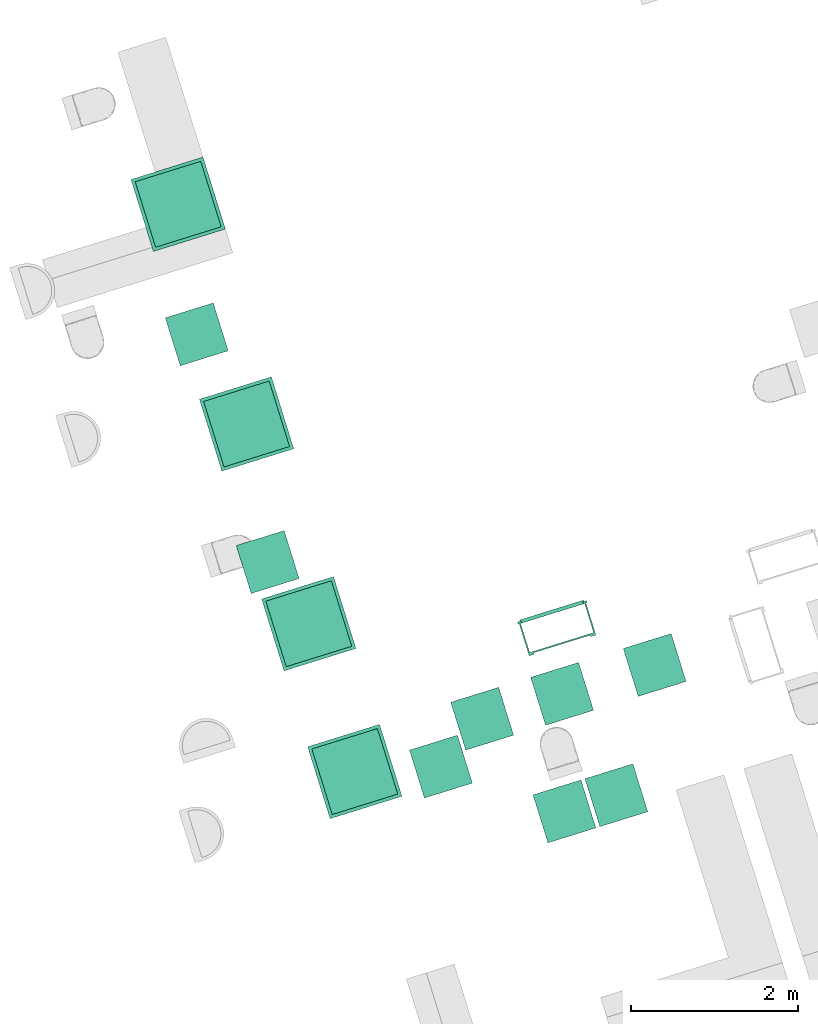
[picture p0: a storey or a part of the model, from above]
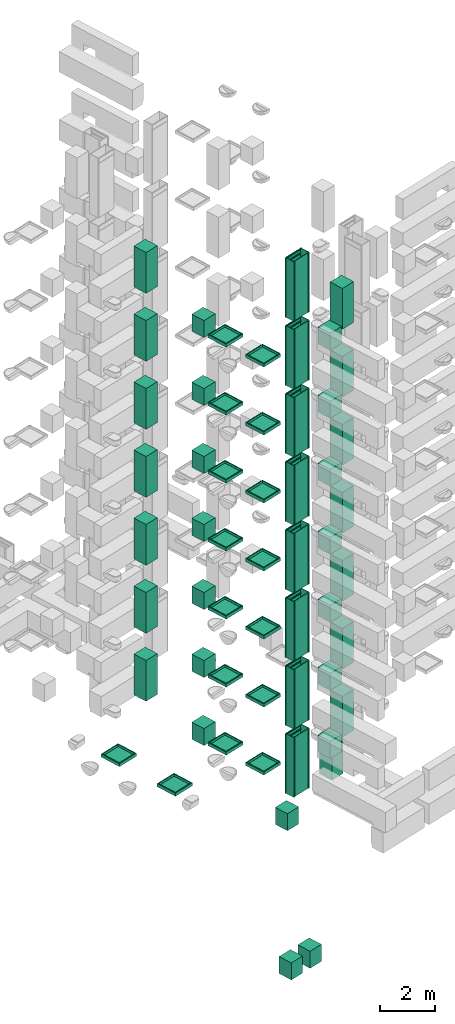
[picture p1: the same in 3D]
Properties of the parts of a building model (IFC4), part 1 of 2

# File
Description: ViewDefinition [ReferenceView_V1.2], RevitIdentifiers [ContentGUID: 7b0fba1c-e461-43e6-a004-74300536da52, VersionGUID: 7265df18-267a-4dc0-a71b-dcb3ef465860, NumberOfSaves: 301], Options [Excluded Entities: IfcGroup;], CoordinateReference [CoordinateBase: Survey Point, ProjectSite: Internal]
File name: MiniBIM 3.1 DO_02_VORM.ifc
Time: 2025-11-03T19:47:52+01:00
Organization: VORM Holding B.V.
Written by: IfcOpenShell 0.8.2
Made in: Bonsai 0.8.2

# IfcProject, 0000
LongName: Voorbeelmodel MiniBIM 3.1 DO-fase; Phase: PROJECTFASE

# IfcSite, Schiehaven
RefLatitude: 51, 54, 13, 78253; RefLongitude: 4, 27, 15, 99642; RefElevation: 3.5 m
Pset_SiteCommon - Reference: Project Information

# IfcBuilding, VORM huis
LongName: VORM huis
Pset_BuildingCommon - Reference: Project Information; NumberOfStoreys: 11; IsLandmarked: no
Pset_BuildingElementProxyCommon - Reference: Project Information; IsExternal: no
Pset_BuildingStoreyCommon - Reference: Project Information; AboveGround: no
Pset_BuildingSystemCommon - Reference: Project Information

# IfcBuildingStorey: Level:Level bouwniveau (PBP) (11)
In: VORM huis
Pset_BuildingStoreyCommon - Reference: Level bouwniveau (PBP)
Name | LongName | Elevation (m) | EntranceLevel | AboveGround
-1 kelder | -1 kelder | -3.2 | no | no
00 begane grond | begane grond | 0 | yes | yes
01 eerste verdieping | 01 eerste verdieping | 3.9 | no | yes
02 tweede verdieping | 02 tweede verdieping | 6.9 | no | yes
03 derde verdieping | 03 derde verdieping | 9.9 | no | yes
04 vierde verdieping | 04 vierde verdieping | 12.9 | no | yes
05 vijfde verdieping | 05 vijfde verdieping | 15.9 | no | yes
06 zesde verdieping | 06 zesde verdieping | 18.9 | no | yes
07 zevende verdieping | 07 zevende verdieping | 21.9 | no | yes
08 achtste verdieping | 08 achtste verdieping | 24.9 | no | yes
09 negende verdieping | 09 negende verdieping | 27.9 | no | yes

# IfcBoiler: NLRS_51_ME_WB_warmtepomp_gen:generiek (44)
Type - Classification: 51.51 (NL-SfB); Material: <Unnamed>
Pset_BoilerTypeCommon - Reference: generiek; sets with these values: 2
Name (NLRS_51_ME_WB_warmtepomp_gen:generiek:...)
1530201
1530227
1530253
1530279
1530305
1530357
1530409
1560085
1560111
1560137
1560163
1560189
1560241
1560293
1578360
1600198
1600224
1600250
1600276
1600302
1600354
1600406
1601616
1601805
1601994
1602183
1602372
1602565
1605335
1605360
1605385
1605410
1605435
1605485
1605535
1609133
1609161
1609189
1609217
1609245
1609301
1609357
1668816
1668842

# IfcBuildingElementProxy: VORM_coordinatiepunt:CRS-coordinatiepunt, CRS-coordinatiepunt
In: 00 begane grond
Type - Classification: 00.00 (NL-SfB); Material: Blauw, Wit
Pset_BuildingElementProxyCommon - IsExternal: no; Reference: CRS-coordinatiepunt
Pset_EnvironmentalImpactIndicators - Reference: CRS-coordinatiepunt
Qto_BuildingElementProxyQuantities - NetSurfaceArea: 6.92096 m2; NetVolume: 0.458368 m3

# IfcBuildingElementProxy: VORM_coordinatiepunt:Lokaal-coordinatiepunt, Lokaal-coordinatiepunt
In: 00 begane grond
Type - Classification: 00.00 (NL-SfB); Material: Blauw, Wit
Pset_BuildingElementProxyCommon - IsExternal: no; Reference: Lokaal-coordinatiepunt
Pset_EnvironmentalImpactIndicators - Reference: Lokaal-coordinatiepunt
Qto_BuildingElementProxyQuantities - NetSurfaceArea: 7.78088 m2; NetVolume: 1.00022 m3

# IfcDistributionChamberElement: NLRS_61_GM_UN_Jonka meterkast_gen:Jonka_kast (49)
Type - PredefinedType: METERCHAMBER; Classification: 61.51 centrale elektrotechnische voorzieningen; energiedistributie laagspanning ?1kV, voedingsleiding laagspanningshoofdverdeler (NL-SfB); Material: <Unnamed>
Type - Pset_ManufacturerTypeInformation - Manufacturer: Jonka o.g.
Pset_DistributionChamberElementCommon - Reference: Jonka_kast; sets with these values: 2
Qto_DistributionChamberElementBaseQuantities - GrossSurfaceArea: 0.130276 m2; NetSurfaceArea: 15.0923 m2; GrossVolume: 0.000819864 m3; NetVolume: 0.122447 m3
Name (NLRS_61_GM_UN_Jonka meterkast_gen:Jonka_kast:...)
1530198
1530224
1530250
1530276
1530302
1530354
1530406
1557295
1557339
1557385
1560082
1560108
1560134
1560160
1560186
1560238
1560290
1565796
1565820
1565844
1565868
1565892
1565940
1565988
1600199
1600225
1600251
1600277
1600303
1600355
1600407
1605322
1605347
1605372
1605397
1605422
1605472
1605522
1609134
1609162
1609190
1609218
1609246
1609302
1609358
1668766
1668794
1668820
1668847

# IfcDoor: 31_DO_buitendeur dubbel:buitendeur zelfsluitend 30min (4)
In: 00 begane grond
Type - PredefinedType: DOOR; Classification: 31.30 buitenwandopeningen; gevuld met deuren, algemeen (verzamelniveau) (NL-SfB); Material: PD_a_buitenwandopeningen, metaal_aluminium_ntb
Type - Pset_DoorCommon - IsExternal: no; FireRating: 30
OverallHeight: 2.35 m; OverallWidth: 1.965 m
Pset_DoorCommon - Reference: buitendeur zelfsluitend 30min
Pset_EnvironmentalImpactIndicators - Reference: buitendeur zelfsluitend 30min
MiniBIM ILS - BouwwerkNummer: 02
Qto_DoorBaseQuantities - Width: 1.965 m; Height: 2.35 m; Perimeter: 1.965 m; Area: 4.61775 m2
Name | Gebruiksbestemming | Orientatie
Vluchtdeur | Woonfunctie | Oost
3 x Vluchtdeur | Bijeenkomstfunctie | West

# IfcDoor: 31_DO_buitendeur enkel:buitendeur zelfsluitend 30min (2)
In: 00 begane grond
Type - PredefinedType: DOOR; Classification: 31.30 buitenwandopeningen; gevuld met deuren, algemeen (verzamelniveau) (NL-SfB); Material: PD_a_buitenwandopeningen, metaal_aluminium_ntb
Type - Pset_DoorCommon - IsExternal: no; FireRating: 30
OverallHeight: 2.35 m; OverallWidth: 1.05 m
Pset_DoorCommon - Reference: buitendeur zelfsluitend 30min
Pset_EnvironmentalImpactIndicators - Reference: buitendeur zelfsluitend 30min
MiniBIM ILS - BouwwerkNummer: 02; Gebruiksbestemming: Overige gebruiksfunctie
Qto_DoorBaseQuantities - Width: 1.05 m; Height: 2.35 m; Perimeter: 2 m; Area: 2.4675 m2
Name | Orientatie
Vluchtdeur | West
Vluchtdeur | Oost

# IfcDoor: 31_DO_buitendeur enkel:woningtoegangsdeur (3)
In: 00 begane grond
Type - PredefinedType: DOOR; OperationType: REVOLVING; Classification: 31.30 buitenwandopeningen; gevuld met deuren, algemeen (verzamelniveau) (NL-SfB); Material: PD_a_buitenwandopeningen, metaal_aluminium_ntb
Type - Woningtoegangsdeur:1 - PanelOperation: REVOLVING
Type - Pset_DoorCommon - IsExternal: no
OverallHeight: 2.35 m; OverallWidth: 1.05 m
Pset_DoorCommon - Reference: woningtoegangsdeur
Pset_EnvironmentalImpactIndicators - Reference: woningtoegangsdeur
MiniBIM ILS - BouwwerkNummer: 02; Gebruiksbestemming: Woonfunctie; Orientatie: Noord
Qto_DoorBaseQuantities - Width: 1.05 m; Height: 2.35 m; Perimeter: 2 m; Area: 2.4675 m2

# IfcDoor: 32_DO_binnendeur dubbel:binnendeur zelfsluitend 30min (6)
In: 00 begane grond
Type - PredefinedType: DOOR; Classification: 32.30 binnenwandopeningen; gevuld met deuren, algemeen (verzamelniveau) (NL-SfB); Material: PD_a_binnenwandopeningen, metaal_aluminium_ntb
Type - Pset_DoorCommon - IsExternal: no; FireRating: 30
OverallHeight: 2.35 m; OverallWidth: 1.95 m
Pset_DoorCommon - Reference: binnendeur zelfsluitend 30min
Pset_EnvironmentalImpactIndicators - Reference: binnendeur zelfsluitend 30min
Qto_DoorBaseQuantities - Width: 1.95 m; Height: 2.35 m; Perimeter: 1.95 m; Area: 4.5825 m2

# IfcDoor: 32_DO_binnendeur enkel:binnendeur (359)
Type - PredefinedType: DOOR; OperationType: REVOLVING; Classification: 32.30 binnenwandopeningen; gevuld met deuren, algemeen (verzamelniveau) (NL-SfB); Material: PD_a_binnenwandopeningen, metaal_aluminium_ntb
Type - Binnendeur:1 - PanelOperation: REVOLVING
Type - Pset_DoorCommon - IsExternal: no
OverallHeight: 2.35 m; OverallWidth: 1.05 m
Pset_DoorCommon - Reference: binnendeur
Pset_EnvironmentalImpactIndicators - Reference: binnendeur
Qto_DoorBaseQuantities - Width: 1.05 m; Height: 2.35 m; Perimeter: 2 m; Area: 2.4675 m2
Name | In
41 x Binnendeur | 02 tweede verdieping
41 x Binnendeur | 03 derde verdieping
41 x Binnendeur | 04 vierde verdieping
41 x Binnendeur | 05 vijfde verdieping
41 x Binnendeur | 06 zesde verdieping
41 x Binnendeur | 07 zevende verdieping
41 x Binnendeur | 08 achtste verdieping
49 x Binnendeur | 01 eerste verdieping
23 x Binnendeur | 00 begane grond

# IfcDoor: 32_DO_binnendeur enkel:binnendeur zelfsluitend 30min (45)
Type - PredefinedType: DOOR; Classification: 32.30 binnenwandopeningen; gevuld met deuren, algemeen (verzamelniveau) (NL-SfB); Material: PD_a_binnenwandopeningen, metaal_aluminium_ntb
Type - Pset_DoorCommon - IsExternal: no; FireRating: 30
OverallHeight: 2.35 m; OverallWidth: 1.05 m
Pset_DoorCommon - Reference: binnendeur zelfsluitend 30min
Pset_EnvironmentalImpactIndicators - Reference: binnendeur zelfsluitend 30min
Qto_DoorBaseQuantities - Width: 1.05 m; Height: 2.35 m; Perimeter: 2 m; Area: 2.4675 m2
Name | In | BouwwerkNummer
4 x Vluchtdeur | 02 tweede verdieping | 01
4 x Vluchtdeur | 03 derde verdieping | 01
4 x Vluchtdeur | 04 vierde verdieping | 01
4 x Vluchtdeur | 05 vijfde verdieping | 01
4 x Vluchtdeur | 06 zesde verdieping | 01
4 x Vluchtdeur | 07 zevende verdieping | 01
4 x Vluchtdeur | 01 eerste verdieping | 01
4 x Vluchtdeur | 08 achtste verdieping | 01
2 x Vluchtdeur | -1 kelder | 01
6 x Vluchtdeur | -1 kelder
4 x Vluchtdeur | 00 begane grond | 01
Vluchtdeur | 00 begane grond

# IfcDoor: 32_DO_binnendeur enkel:kastdeur (3)
In: 00 begane grond
Type - PredefinedType: DOOR; OperationType: REVOLVING; Classification: 32.30 binnenwandopeningen; gevuld met deuren, algemeen (verzamelniveau) (NL-SfB); Material: PD_a_binnenwandopeningen, metaal_aluminium_ntb
Type - Binnendeur:1 - PanelOperation: REVOLVING
Type - Pset_DoorCommon - IsExternal: no
OverallHeight: 2.35 m; OverallWidth: 0.95 m
Pset_DoorCommon - Reference: kastdeur
Pset_EnvironmentalImpactIndicators - Reference: kastdeur
Qto_DoorBaseQuantities - Width: 0.95 m; Height: 2.35 m; Perimeter: 1.8 m; Area: 2.2325 m2

# IfcDoor: 32_DO_binnendeur enkel:woningtoegangsdeur (46)
Type - PredefinedType: DOOR; OperationType: REVOLVING; Classification: 32.30 binnenwandopeningen; gevuld met deuren, algemeen (verzamelniveau) (NL-SfB); Material: PD_a_binnenwandopeningen, metaal_aluminium_ntb
Type - Woningtoegangsdeur:1 - PanelOperation: REVOLVING
Type - Pset_DoorCommon - IsExternal: no
OverallHeight: 2.35 m; OverallWidth: 1.05 m
Pset_DoorCommon - Reference: woningtoegangsdeur
Pset_EnvironmentalImpactIndicators - Reference: woningtoegangsdeur
MiniBIM ILS - BouwwerkNummer: 02
Qto_DoorBaseQuantities - Width: 1.05 m; Height: 2.35 m; Perimeter: 2 m; Area: 2.4675 m2
Name | In
6 x Woningtoegangsdeur | 02 tweede verdieping
6 x Woningtoegangsdeur | 03 derde verdieping
6 x Woningtoegangsdeur | 04 vierde verdieping
6 x Woningtoegangsdeur | 05 vijfde verdieping
6 x Woningtoegangsdeur | 06 zesde verdieping
6 x Woningtoegangsdeur | 07 zevende verdieping
6 x Woningtoegangsdeur | 08 achtste verdieping
4 x Woningtoegangsdeur | 01 eerste verdieping

# IfcDoor: 66_WI_liftdeur:brandweerlift - eenzijdig toegankelijk (2)
In: -1 kelder
Type - PredefinedType: DOOR; Classification: 66.10 transport; liftinstallaties, algemeen (verzamelniveau) (NL-SfB); Material: metaal_aluminium_ntb
OverallHeight: 2.4 m; OverallWidth: 1 m
Pset_DoorCommon - IsExternal: no; Reference: brandweerlift - eenzijdig toegankelijk
Pset_EnvironmentalImpactIndicators - Reference: brandweerlift - eenzijdig toegankelijk
MiniBIM ILS - BouwwerkNummer: 01
Qto_DoorBaseQuantities - Width: 1 m; Height: 2.4 m; Perimeter: 1.1 m; Area: 2.4 m2

# IfcDoor: 66_WI_liftdeur:brandweerlift - tweezijdig toegankelijk (18)
Type - PredefinedType: DOOR; Classification: 66.10 transport; liftinstallaties, algemeen (verzamelniveau) (NL-SfB); Material: metaal_aluminium_ntb
OverallHeight: 2.4 m; OverallWidth: 1 m
Pset_DoorCommon - IsExternal: no; Reference: brandweerlift - tweezijdig toegankelijk
Pset_EnvironmentalImpactIndicators - Reference: brandweerlift - tweezijdig toegankelijk
MiniBIM ILS - BouwwerkNummer: 01
Qto_DoorBaseQuantities - Width: 1 m; Height: 2.4 m; Perimeter: 1.1 m; Area: 2.4 m2
Name | In
2 x Brandweerlift | 02 tweede verdieping
2 x Brandweerlift | 03 derde verdieping
2 x Brandweerlift | 04 vierde verdieping
2 x Brandweerlift | 05 vijfde verdieping
2 x Brandweerlift | 06 zesde verdieping
2 x Brandweerlift | 07 zevende verdieping
2 x Brandweerlift | 01 eerste verdieping
2 x Brandweerlift | 08 achtste verdieping
2 x Brandweerlift | 00 begane grond

# IfcElectricAppliance: NLRS_85_SE_UN_opstelplaats wasmachine_gen:wasdroger (48)
Type - PredefinedType: TUMBLEDRYER; Classification: 85.11 losse schoonmaakinventaris; standaard, schoonmaakapparatuur (NL-SfB); Material: <Unnamed>
Pset_ElectricApplianceTypeCommon - Reference: wasdroger; sets with these values: 2
Name (NLRS_85_SE_UN_opstelplaats wasmachine_gen:wasdroger:...)
1530205
1530231
1530257
1530283
1530309
1530361
1530413
1560088
1560114
1560140
1560166
1560192
1560244
1560296
1565801
1565825
1565849
1565873
1565897
1565945
1565993
1600197
1600223
1600249
1600275
1600301
1600353
1600405
1605334
1605359
1605384
1605409
1605434
1605484
1605534
1609132
1609160
1609188
1609216
1609244
1609300
1609356
1668765
1668793
1668819
1668846
1743114
1743329

# IfcFurniture: NLRS_73_CASE_LB_keukenblok L a_gen:keukenblok hoek 2700x2100 (25)
Type - Classification: 73.11 vaste keukenvoorzieningen; standaard, keukenmeubilering (NL-SfB); Material: <Unnamed>
Pset_EnvironmentalImpactIndicators - Reference: keukenblok hoek 2700x2100; sets with these values: 2
Name (NLRS_73_CASE_LB_keukenblok L a_gen:keukenblok hoek 2700x2100:...)
1530204
1530230
1530256
1530282
1530308
1530360
1530412
1560087
1560113
1560139
1560165
1560191
1560243
1560295
1600216
1600242
1600268
1600294
1600320
1600372
1600424
1668790
1668871
1731758
1731790

# IfcFurniture: NLRS_73_CASE_LB_keukenblok a_gen:keukenblok 3200 (24)
Type - Classification: 73.11 vaste keukenvoorzieningen; standaard, keukenmeubilering (NL-SfB); Material: <Unnamed>
Pset_EnvironmentalImpactIndicators - Reference: keukenblok 3200; sets with these values: 2
Name (NLRS_73_CASE_LB_keukenblok a_gen:keukenblok 3200:...)
1557281
1557325
1557371
1570071
1570076
1570081
1570086
1570091
1570101
1570111
1605328
1605353
1605378
1605403
1605428
1605478
1605528
1609146
1609174
1609202
1609230
1609258
1609314
1609370

# IfcOpeningElement (726)
PredefinedType: OPENING
Name | In | Depth (m) | Height (m) | Width (m)
3 x Constructieve wand | 02 tweede verdieping | 0.25 | 2.4 | 1.1 | Pset_EnvironmentalImpactIndicators - Reference: 28_WA_skelet_wand 250mm_gen; sets with these values: 2
3 x Constructieve wand | 02 tweede verdieping | 0.25 | 2.4 | 1.2 | Pset_EnvironmentalImpactIndicators - Reference: 28_WA_skelet_wand 250mm_gen; sets with these values: 2
Constructieve vloer | 02 tweede verdieping |  | 2.75 | 3.5 | Pset_EnvironmentalImpactIndicators - Reference: 28_FL_skelet_vloer 250mm; sets with these values: 2
Constructieve vloer | 02 tweede verdieping |  | 1.2 | 3.3 | Pset_EnvironmentalImpactIndicators - Reference: 28_FL_skelet_vloer 250mm; sets with these values: 2
Constructieve vloer | 02 tweede verdieping |  | 0.3 | 0.85 | Pset_EnvironmentalImpactIndicators - Reference: 28_FL_skelet_vloer 250mm; sets with these values: 2
Constructieve vloer | 02 tweede verdieping |  | 0.85 | 0.3 | Pset_EnvironmentalImpactIndicators - Reference: 28_FL_skelet_vloer 250mm; sets with these values: 2
Constructieve vloer | 02 tweede verdieping |  | 1.25 | 0.3 | Pset_EnvironmentalImpactIndicators - Reference: 28_FL_skelet_vloer 250mm; sets with these values: 2
Constructieve vloer | 02 tweede verdieping |  | 0.3 | 1.40216 | Pset_EnvironmentalImpactIndicators - Reference: 28_FL_skelet_vloer 250mm; sets with these values: 2
Constructieve vloer | 02 tweede verdieping |  | 0.275 | 1.25 | Pset_EnvironmentalImpactIndicators - Reference: 28_FL_skelet_vloer 250mm; sets with these values: 2
Constructieve vloer | 02 tweede verdieping |  | 0.3 | 1.25 | Pset_EnvironmentalImpactIndicators - Reference: 28_FL_skelet_vloer 250mm; sets with these values: 2
3 x Constructieve wand | 03 derde verdieping | 0.25 | 2.4 | 1.1 | Pset_EnvironmentalImpactIndicators - Reference: 28_WA_skelet_wand 250mm_gen; sets with these values: 2
3 x Constructieve wand | 03 derde verdieping | 0.25 | 2.4 | 1.2 | Pset_EnvironmentalImpactIndicators - Reference: 28_WA_skelet_wand 250mm_gen; sets with these values: 2
Constructieve vloer | 03 derde verdieping |  | 2.75 | 3.5 | Pset_EnvironmentalImpactIndicators - Reference: 28_FL_skelet_vloer 250mm; sets with these values: 2
Constructieve vloer | 03 derde verdieping |  | 1.2 | 3.3 | Pset_EnvironmentalImpactIndicators - Reference: 28_FL_skelet_vloer 250mm; sets with these values: 2
Constructieve vloer | 03 derde verdieping |  | 0.3 | 0.85 | Pset_EnvironmentalImpactIndicators - Reference: 28_FL_skelet_vloer 250mm; sets with these values: 2
Constructieve vloer | 03 derde verdieping |  | 0.85 | 0.3 | Pset_EnvironmentalImpactIndicators - Reference: 28_FL_skelet_vloer 250mm; sets with these values: 2
Constructieve vloer | 03 derde verdieping |  | 1.25 | 0.3 | Pset_EnvironmentalImpactIndicators - Reference: 28_FL_skelet_vloer 250mm; sets with these values: 2
Constructieve vloer | 03 derde verdieping |  | 0.3 | 1.40216 | Pset_EnvironmentalImpactIndicators - Reference: 28_FL_skelet_vloer 250mm; sets with these values: 2
Constructieve vloer | 03 derde verdieping |  | 0.275 | 1.25 | Pset_EnvironmentalImpactIndicators - Reference: 28_FL_skelet_vloer 250mm; sets with these values: 2
Constructieve vloer | 03 derde verdieping |  | 0.3 | 1.25 | Pset_EnvironmentalImpactIndicators - Reference: 28_FL_skelet_vloer 250mm; sets with these values: 2
3 x Constructieve wand | 04 vierde verdieping | 0.25 | 2.4 | 1.1 | Pset_EnvironmentalImpactIndicators - Reference: 28_WA_skelet_wand 250mm_gen; sets with these values: 2
3 x Constructieve wand | 04 vierde verdieping | 0.25 | 2.4 | 1.2 | Pset_EnvironmentalImpactIndicators - Reference: 28_WA_skelet_wand 250mm_gen; sets with these values: 2
Constructieve vloer | 04 vierde verdieping |  | 2.75 | 3.5 | Pset_EnvironmentalImpactIndicators - Reference: 28_FL_skelet_vloer 250mm; sets with these values: 2
Constructieve vloer | 04 vierde verdieping |  | 1.2 | 3.3 | Pset_EnvironmentalImpactIndicators - Reference: 28_FL_skelet_vloer 250mm; sets with these values: 2
Constructieve vloer | 04 vierde verdieping |  | 0.3 | 0.85 | Pset_EnvironmentalImpactIndicators - Reference: 28_FL_skelet_vloer 250mm; sets with these values: 2
Constructieve vloer | 04 vierde verdieping |  | 0.85 | 0.3 | Pset_EnvironmentalImpactIndicators - Reference: 28_FL_skelet_vloer 250mm; sets with these values: 2
Constructieve vloer | 04 vierde verdieping |  | 1.25 | 0.3 | Pset_EnvironmentalImpactIndicators - Reference: 28_FL_skelet_vloer 250mm; sets with these values: 2
Constructieve vloer | 04 vierde verdieping |  | 0.3 | 1.40216 | Pset_EnvironmentalImpactIndicators - Reference: 28_FL_skelet_vloer 250mm; sets with these values: 2
Constructieve vloer | 04 vierde verdieping |  | 0.275 | 1.25 | Pset_EnvironmentalImpactIndicators - Reference: 28_FL_skelet_vloer 250mm; sets with these values: 2
Constructieve vloer | 04 vierde verdieping |  | 0.3 | 1.25 | Pset_EnvironmentalImpactIndicators - Reference: 28_FL_skelet_vloer 250mm; sets with these values: 2
3 x Constructieve wand | 05 vijfde verdieping | 0.25 | 2.4 | 1.1 | Pset_EnvironmentalImpactIndicators - Reference: 28_WA_skelet_wand 250mm_gen; sets with these values: 2
3 x Constructieve wand | 05 vijfde verdieping | 0.25 | 2.4 | 1.2 | Pset_EnvironmentalImpactIndicators - Reference: 28_WA_skelet_wand 250mm_gen; sets with these values: 2
Constructieve vloer | 05 vijfde verdieping |  | 2.75 | 3.5 | Pset_EnvironmentalImpactIndicators - Reference: 28_FL_skelet_vloer 250mm; sets with these values: 2
Constructieve vloer | 05 vijfde verdieping |  | 1.2 | 3.3 | Pset_EnvironmentalImpactIndicators - Reference: 28_FL_skelet_vloer 250mm; sets with these values: 2
Constructieve vloer | 05 vijfde verdieping |  | 0.3 | 0.85 | Pset_EnvironmentalImpactIndicators - Reference: 28_FL_skelet_vloer 250mm; sets with these values: 2
Constructieve vloer | 05 vijfde verdieping |  | 0.85 | 0.3 | Pset_EnvironmentalImpactIndicators - Reference: 28_FL_skelet_vloer 250mm; sets with these values: 2
Constructieve vloer | 05 vijfde verdieping |  | 1.25 | 0.3 | Pset_EnvironmentalImpactIndicators - Reference: 28_FL_skelet_vloer 250mm; sets with these values: 2
Constructieve vloer | 05 vijfde verdieping |  | 0.3 | 1.40216 | Pset_EnvironmentalImpactIndicators - Reference: 28_FL_skelet_vloer 250mm; sets with these values: 2
Constructieve vloer | 05 vijfde verdieping |  | 0.275 | 1.25 | Pset_EnvironmentalImpactIndicators - Reference: 28_FL_skelet_vloer 250mm; sets with these values: 2
Constructieve vloer | 05 vijfde verdieping |  | 0.3 | 1.25 | Pset_EnvironmentalImpactIndicators - Reference: 28_FL_skelet_vloer 250mm; sets with these values: 2
3 x Constructieve wand | 06 zesde verdieping | 0.25 | 2.4 | 1.1 | Pset_EnvironmentalImpactIndicators - Reference: 28_WA_skelet_wand 250mm_gen; sets with these values: 2
3 x Constructieve wand | 06 zesde verdieping | 0.25 | 2.4 | 1.2 | Pset_EnvironmentalImpactIndicators - Reference: 28_WA_skelet_wand 250mm_gen; sets with these values: 2
Constructieve vloer | 06 zesde verdieping |  | 2.75 | 3.5 | Pset_EnvironmentalImpactIndicators - Reference: 28_FL_skelet_vloer 250mm; sets with these values: 2
Constructieve vloer | 06 zesde verdieping |  | 1.2 | 3.3 | Pset_EnvironmentalImpactIndicators - Reference: 28_FL_skelet_vloer 250mm; sets with these values: 2
Constructieve vloer | 06 zesde verdieping |  | 0.3 | 0.85 | Pset_EnvironmentalImpactIndicators - Reference: 28_FL_skelet_vloer 250mm; sets with these values: 2
Constructieve vloer | 06 zesde verdieping |  | 0.85 | 0.3 | Pset_EnvironmentalImpactIndicators - Reference: 28_FL_skelet_vloer 250mm; sets with these values: 2
Constructieve vloer | 06 zesde verdieping |  | 1.25 | 0.3 | Pset_EnvironmentalImpactIndicators - Reference: 28_FL_skelet_vloer 250mm; sets with these values: 2
Constructieve vloer | 06 zesde verdieping |  | 0.3 | 1.40216 | Pset_EnvironmentalImpactIndicators - Reference: 28_FL_skelet_vloer 250mm; sets with these values: 2
Constructieve vloer | 06 zesde verdieping |  | 0.275 | 1.25 | Pset_EnvironmentalImpactIndicators - Reference: 28_FL_skelet_vloer 250mm; sets with these values: 2
Constructieve vloer | 06 zesde verdieping |  | 0.3 | 1.25 | Pset_EnvironmentalImpactIndicators - Reference: 28_FL_skelet_vloer 250mm; sets with these values: 2
3 x Constructieve wand | 07 zevende verdieping | 0.25 | 2.4 | 1.1 | Pset_EnvironmentalImpactIndicators - Reference: 28_WA_skelet_wand 250mm_gen; sets with these values: 2
3 x Constructieve wand | 07 zevende verdieping | 0.25 | 2.4 | 1.2 | Pset_EnvironmentalImpactIndicators - Reference: 28_WA_skelet_wand 250mm_gen; sets with these values: 2
Constructieve vloer | 07 zevende verdieping |  | 2.75 | 3.5 | Pset_EnvironmentalImpactIndicators - Reference: 28_FL_skelet_vloer 250mm; sets with these values: 2
Constructieve vloer | 07 zevende verdieping |  | 1.2 | 3.3 | Pset_EnvironmentalImpactIndicators - Reference: 28_FL_skelet_vloer 250mm; sets with these values: 2
Constructieve vloer | 07 zevende verdieping |  | 0.3 | 0.85 | Pset_EnvironmentalImpactIndicators - Reference: 28_FL_skelet_vloer 250mm; sets with these values: 2
Constructieve vloer | 07 zevende verdieping |  | 0.85 | 0.3 | Pset_EnvironmentalImpactIndicators - Reference: 28_FL_skelet_vloer 250mm; sets with these values: 2
Constructieve vloer | 07 zevende verdieping |  | 1.25 | 0.3 | Pset_EnvironmentalImpactIndicators - Reference: 28_FL_skelet_vloer 250mm; sets with these values: 2
Constructieve vloer | 07 zevende verdieping |  | 0.3 | 1.40216 | Pset_EnvironmentalImpactIndicators - Reference: 28_FL_skelet_vloer 250mm; sets with these values: 2
Constructieve vloer | 07 zevende verdieping |  | 0.275 | 1.25 | Pset_EnvironmentalImpactIndicators - Reference: 28_FL_skelet_vloer 250mm; sets with these values: 2
Constructieve vloer | 07 zevende verdieping |  | 0.3 | 1.25 | Pset_EnvironmentalImpactIndicators - Reference: 28_FL_skelet_vloer 250mm; sets with these values: 2
4 x Constructieve wand | 01 eerste verdieping | 0.25 | 2.4 | 2.4 | Pset_EnvironmentalImpactIndicators - Reference: 28_WA_skelet_wand 250mm_gen; sets with these values: 2
4 x Constructieve wand | 01 eerste verdieping | 0.25 | 2.4 | 1.25 | Pset_EnvironmentalImpactIndicators - Reference: 28_WA_skelet_wand 250mm_gen; sets with these values: 2
2 x Constructieve wand | 01 eerste verdieping | 0.25 | 2.4 | 1.5 | Pset_EnvironmentalImpactIndicators - Reference: 28_WA_skelet_wand 250mm_gen; sets with these values: 2
Constructieve vloer | 01 eerste verdieping |  | 2.75 | 3.5 | Pset_EnvironmentalImpactIndicators - Reference: 28_FL_skelet_vloer 250mm; sets with these values: 2
Constructieve vloer | 01 eerste verdieping |  | 1.2 | 3.3 | Pset_EnvironmentalImpactIndicators - Reference: 28_FL_skelet_vloer 250mm; sets with these values: 2
Constructieve vloer | 01 eerste verdieping |  | 0.3 | 0.85 | Pset_EnvironmentalImpactIndicators - Reference: 28_FL_skelet_vloer 250mm; sets with these values: 2
3 x Constructieve vloer | 01 eerste verdieping |  | 0.25 | 0.8 | Pset_EnvironmentalImpactIndicators - Reference: 28_FL_skelet_vloer 250mm; sets with these values: 2
3 x Constructieve vloer | 01 eerste verdieping |  | 3.038 | 0.95 | Pset_EnvironmentalImpactIndicators - Reference: 28_FL_skelet_vloer 250mm; sets with these values: 2
Constructieve vloer | 01 eerste verdieping | Pset_EnvironmentalImpactIndicators - Reference: 28_FL_skelet_vloer 250mm; sets with these values: 2; Qto_OpeningElementBaseQuantities - Area: 8.664 m2
3 x Constructieve wand | 08 achtste verdieping | 0.25 | 2.4 | 1.1 | Pset_EnvironmentalImpactIndicators - Reference: 28_WA_skelet_wand 250mm_gen; sets with these values: 2
3 x Constructieve wand | 08 achtste verdieping | 0.25 | 2.4 | 1.2 | Pset_EnvironmentalImpactIndicators - Reference: 28_WA_skelet_wand 250mm_gen; sets with these values: 2
Constructieve vloer | 08 achtste verdieping |  | 2.75 | 3.5 | Pset_EnvironmentalImpactIndicators - Reference: 28_FL_skelet_vloer 250mm; sets with these values: 2
Constructieve vloer | 08 achtste verdieping |  | 1.2 | 3.3 | Pset_EnvironmentalImpactIndicators - Reference: 28_FL_skelet_vloer 250mm; sets with these values: 2
Constructieve vloer | 08 achtste verdieping |  | 0.3 | 0.85 | Pset_EnvironmentalImpactIndicators - Reference: 28_FL_skelet_vloer 250mm; sets with these values: 2
Constructieve vloer | 08 achtste verdieping |  | 0.85 | 0.3 | Pset_EnvironmentalImpactIndicators - Reference: 28_FL_skelet_vloer 250mm; sets with these values: 2
Constructieve vloer | 08 achtste verdieping |  | 1.25 | 0.3 | Pset_EnvironmentalImpactIndicators - Reference: 28_FL_skelet_vloer 250mm; sets with these values: 2
Constructieve vloer | 08 achtste verdieping |  | 0.3 | 1.40216 | Pset_EnvironmentalImpactIndicators - Reference: 28_FL_skelet_vloer 250mm; sets with these values: 2
Constructieve vloer | 08 achtste verdieping |  | 0.275 | 1.25 | Pset_EnvironmentalImpactIndicators - Reference: 28_FL_skelet_vloer 250mm; sets with these values: 2
Constructieve vloer | 08 achtste verdieping |  | 0.3 | 1.25 | Pset_EnvironmentalImpactIndicators - Reference: 28_FL_skelet_vloer 250mm; sets with these values: 2
Dakvloer | 09 negende verdieping |  | 2.75 | 3.5 | Pset_EnvironmentalImpactIndicators - Reference: 28_FL_skelet_dakvloer 250mm; sets with these values: 2
Vluchtdeur | -1 kelder | 1.05 | 2.35 | 0.1 | Pset_EnvironmentalImpactIndicators - Reference: binnendeur zelfsluitend 30min; sets with these values: 2; Classification: 32.30 binnenwandopeningen; gevuld met deuren, algemeen (verzamelniveau) (NL-SfB)
2 x Vluchtdeur | 00 begane grond | 3.048 | 2.35 | 1.05 | Pset_EnvironmentalImpactIndicators - Reference: buitendeur zelfsluitend 30min; sets with these values: 2; Classification: 31.30 buitenwandopeningen; gevuld met deuren, algemeen (verzamelniveau) (NL-SfB)
4 x Vluchtdeur | 00 begane grond | 3.048 | 2.35 | 1.965 | Pset_EnvironmentalImpactIndicators - Reference: buitendeur zelfsluitend 30min; sets with these values: 2; Classification: 31.30 buitenwandopeningen; gevuld met deuren, algemeen (verzamelniveau) (NL-SfB)
Constructieve vloer | 00 begane grond |  | 2.75 | 3.5 | Pset_EnvironmentalImpactIndicators - Reference: 28_FL_skelet_vloer 250mm; sets with these values: 2
Constructieve vloer | 00 begane grond |  | 1.2 | 3.3 | Pset_EnvironmentalImpactIndicators - Reference: 28_FL_skelet_vloer 250mm; sets with these values: 2
2 x Constructieve wand | 00 begane grond | 0.25 | 2.4 | 2.1 | Pset_EnvironmentalImpactIndicators - Reference: 28_WA_skelet_wand 250mm_gen; sets with these values: 2
2 x Constructieve wand | 00 begane grond | 0.25 | 2.4 | 1.5 | Pset_EnvironmentalImpactIndicators - Reference: 28_WA_skelet_wand 250mm_gen; sets with these values: 2
2 x Constructieve wand | 00 begane grond | 0.25 | 2.4 | 2.05 | Pset_EnvironmentalImpactIndicators - Reference: 28_WA_skelet_wand 250mm_gen; sets with these values: 2
Funderingvloer | -1 kelder |  | 2.75 | 3.5 | Pset_EnvironmentalImpactIndicators - Reference: 13_FL_funderingvloer 250mm; sets with these values: 2
6 x Binnendeur | 02 tweede verdieping | 1.05 | 2.35 | 0.1 | Pset_EnvironmentalImpactIndicators - Reference: binnendeur; sets with these values: 2; Classification: 32.30 binnenwandopeningen; gevuld met deuren, algemeen (verzamelniveau) (NL-SfB)
2 x Binnenwand:1 | 02 tweede verdieping |  |  | 0.1 | Pset_EnvironmentalImpactIndicators - Reference: 22_WA_afbouw_binnenwand 100mm_gen; sets with these values: 2; Qto_OpeningElementBaseQuantities - Area: 6.0575 m2; Volume: 1.98737 m3; Classification: 22.10 binnenwanden; niet constructief, algemeen (verzamelniveau) (NL-SfB)
6 x Binnendeur | 03 derde verdieping | 1.05 | 2.35 | 0.1 | Pset_EnvironmentalImpactIndicators - Reference: binnendeur; sets with these values: 2; Classification: 32.30 binnenwandopeningen; gevuld met deuren, algemeen (verzamelniveau) (NL-SfB)
2 x Binnenwand:1 | 03 derde verdieping |  |  | 0.1 | Pset_EnvironmentalImpactIndicators - Reference: 22_WA_afbouw_binnenwand 100mm_gen; sets with these values: 2; Qto_OpeningElementBaseQuantities - Area: 6.0575 m2; Volume: 1.98737 m3; Classification: 22.10 binnenwanden; niet constructief, algemeen (verzamelniveau) (NL-SfB)
6 x Binnendeur | 04 vierde verdieping | 1.05 | 2.35 | 0.1 | Pset_EnvironmentalImpactIndicators - Reference: binnendeur; sets with these values: 2; Classification: 32.30 binnenwandopeningen; gevuld met deuren, algemeen (verzamelniveau) (NL-SfB)
2 x Binnenwand:1 | 04 vierde verdieping |  |  | 0.1 | Pset_EnvironmentalImpactIndicators - Reference: 22_WA_afbouw_binnenwand 100mm_gen; sets with these values: 2; Qto_OpeningElementBaseQuantities - Area: 6.0575 m2; Volume: 1.98737 m3; Classification: 22.10 binnenwanden; niet constructief, algemeen (verzamelniveau) (NL-SfB)
6 x Binnendeur | 05 vijfde verdieping | 1.05 | 2.35 | 0.1 | Pset_EnvironmentalImpactIndicators - Reference: binnendeur; sets with these values: 2; Classification: 32.30 binnenwandopeningen; gevuld met deuren, algemeen (verzamelniveau) (NL-SfB)
2 x Binnenwand:1 | 05 vijfde verdieping |  |  | 0.1 | Pset_EnvironmentalImpactIndicators - Reference: 22_WA_afbouw_binnenwand 100mm_gen; sets with these values: 2; Qto_OpeningElementBaseQuantities - Area: 6.0575 m2; Volume: 1.98737 m3; Classification: 22.10 binnenwanden; niet constructief, algemeen (verzamelniveau) (NL-SfB)
6 x Binnendeur | 06 zesde verdieping | 1.05 | 2.35 | 0.1 | Pset_EnvironmentalImpactIndicators - Reference: binnendeur; sets with these values: 2; Classification: 32.30 binnenwandopeningen; gevuld met deuren, algemeen (verzamelniveau) (NL-SfB)
2 x Binnenwand:1 | 06 zesde verdieping |  |  | 0.1 | Pset_EnvironmentalImpactIndicators - Reference: 22_WA_afbouw_binnenwand 100mm_gen; sets with these values: 2; Qto_OpeningElementBaseQuantities - Area: 6.0575 m2; Volume: 1.98737 m3; Classification: 22.10 binnenwanden; niet constructief, algemeen (verzamelniveau) (NL-SfB)
6 x Binnendeur | 07 zevende verdieping | 1.05 | 2.35 | 0.1 | Pset_EnvironmentalImpactIndicators - Reference: binnendeur; sets with these values: 2; Classification: 32.30 binnenwandopeningen; gevuld met deuren, algemeen (verzamelniveau) (NL-SfB)
2 x Binnenwand:1 | 07 zevende verdieping |  |  | 0.1 | Pset_EnvironmentalImpactIndicators - Reference: 22_WA_afbouw_binnenwand 100mm_gen; sets with these values: 2; Qto_OpeningElementBaseQuantities - Area: 6.0575 m2; Volume: 1.98737 m3; Classification: 22.10 binnenwanden; niet constructief, algemeen (verzamelniveau) (NL-SfB)
6 x Binnendeur | 08 achtste verdieping | 1.05 | 2.35 | 0.1 | Pset_EnvironmentalImpactIndicators - Reference: binnendeur; sets with these values: 2; Classification: 32.30 binnenwandopeningen; gevuld met deuren, algemeen (verzamelniveau) (NL-SfB)
2 x Binnenwand:1 | 08 achtste verdieping |  |  | 0.1 | Pset_EnvironmentalImpactIndicators - Reference: 22_WA_afbouw_binnenwand 100mm_gen; sets with these values: 2; Qto_OpeningElementBaseQuantities - Area: 6.0575 m2; Volume: 1.98737 m3; Classification: 22.10 binnenwanden; niet constructief, algemeen (verzamelniveau) (NL-SfB)
3 x Woningtoegangsdeur | 00 begane grond | 3.048 | 2.35 | 1.05 | Pset_EnvironmentalImpactIndicators - Reference: woningtoegangsdeur; sets with these values: 2; Classification: 31.30 buitenwandopeningen; gevuld met deuren, algemeen (verzamelniveau) (NL-SfB)
3 x Woningtoegangsdeur | 00 begane grond | 1.05 | 2.35 | 0.3 | Pset_EnvironmentalImpactIndicators - Reference: woningtoegangsdeur; sets with these values: 2; Classification: 31.30 buitenwandopeningen; gevuld met deuren, algemeen (verzamelniveau) (NL-SfB)
7 x Binnendeur | 01 eerste verdieping | 1.05 | 2.35 | 0.1 | Pset_EnvironmentalImpactIndicators - Reference: binnendeur; sets with these values: 2; Classification: 32.30 binnenwandopeningen; gevuld met deuren, algemeen (verzamelniveau) (NL-SfB)
2 x Binnendeur | 02 tweede verdieping | 0.25 | 1.05 | 2.35
2 x Woningtoegangsdeur | 02 tweede verdieping | 0.25 | 2.35 | 1.05
2 x Brandweerlift | 02 tweede verdieping | 0.75631 | 2.4 | 1
4 x Woningtoegangsdeur | 02 tweede verdieping | 0.25 | 1.05 | 2.35
2 x Vluchtdeur | 02 tweede verdieping | 0.1 | 1.05 | 2.35
2 x Vluchtdeur | 02 tweede verdieping | 0.1 | 2.35 | 1.05
2 x Binnendeur | 03 derde verdieping | 0.25 | 1.05 | 2.35
2 x Woningtoegangsdeur | 03 derde verdieping | 0.25 | 2.35 | 1.05
2 x Brandweerlift | 03 derde verdieping | 0.75631 | 2.4 | 1
4 x Woningtoegangsdeur | 03 derde verdieping | 0.25 | 1.05 | 2.35
2 x Vluchtdeur | 03 derde verdieping | 0.1 | 1.05 | 2.35
2 x Vluchtdeur | 03 derde verdieping | 0.1 | 2.35 | 1.05
2 x Binnendeur | 04 vierde verdieping | 0.25 | 1.05 | 2.35
2 x Woningtoegangsdeur | 04 vierde verdieping | 0.25 | 2.35 | 1.05
2 x Brandweerlift | 04 vierde verdieping | 0.75631 | 2.4 | 1
4 x Woningtoegangsdeur | 04 vierde verdieping | 0.25 | 1.05 | 2.35
2 x Vluchtdeur | 04 vierde verdieping | 0.1 | 1.05 | 2.35
2 x Vluchtdeur | 04 vierde verdieping | 0.1 | 2.35 | 1.05
2 x Binnendeur | 05 vijfde verdieping | 0.25 | 1.05 | 2.35
2 x Woningtoegangsdeur | 05 vijfde verdieping | 0.25 | 2.35 | 1.05
2 x Brandweerlift | 05 vijfde verdieping | 0.75631 | 2.4 | 1
4 x Woningtoegangsdeur | 05 vijfde verdieping | 0.25 | 1.05 | 2.35
2 x Vluchtdeur | 05 vijfde verdieping | 0.1 | 1.05 | 2.35
2 x Vluchtdeur | 05 vijfde verdieping | 0.1 | 2.35 | 1.05
2 x Binnendeur | 06 zesde verdieping | 0.25 | 1.05 | 2.35
2 x Woningtoegangsdeur | 06 zesde verdieping | 0.25 | 2.35 | 1.05
2 x Brandweerlift | 06 zesde verdieping | 0.75631 | 2.4 | 1
4 x Woningtoegangsdeur | 06 zesde verdieping | 0.25 | 1.05 | 2.35
2 x Vluchtdeur | 06 zesde verdieping | 0.1 | 1.05 | 2.35
2 x Vluchtdeur | 06 zesde verdieping | 0.1 | 2.35 | 1.05
2 x Binnendeur | 07 zevende verdieping | 0.25 | 1.05 | 2.35
2 x Woningtoegangsdeur | 07 zevende verdieping | 0.25 | 2.35 | 1.05
2 x Brandweerlift | 07 zevende verdieping | 0.75631 | 2.4 | 1
4 x Woningtoegangsdeur | 07 zevende verdieping | 0.25 | 1.05 | 2.35
2 x Vluchtdeur | 07 zevende verdieping | 0.1 | 1.05 | 2.35
2 x Vluchtdeur | 07 zevende verdieping | 0.1 | 2.35 | 1.05
2 x Brandweerlift | 01 eerste verdieping | 0.75631 | 2.4 | 1
4 x Woningtoegangsdeur | 01 eerste verdieping | 0.25 | 1.05 | 2.35
2 x Vluchtdeur | 01 eerste verdieping | 0.1 | 1.05 | 2.35
2 x Vluchtdeur | 01 eerste verdieping | 0.1 | 2.35 | 1.05
2 x Binnendeur | 08 achtste verdieping | 0.25 | 1.05 | 2.35
2 x Woningtoegangsdeur | 08 achtste verdieping | 0.25 | 2.35 | 1.05
2 x Brandweerlift | 08 achtste verdieping | 0.75631 | 2.4 | 1
4 x Woningtoegangsdeur | 08 achtste verdieping | 0.25 | 1.05 | 2.35
2 x Vluchtdeur | 08 achtste verdieping | 0.1 | 1.05 | 2.35
2 x Vluchtdeur | 08 achtste verdieping | 0.1 | 2.35 | 1.05
2 x Brandweerlift | -1 kelder | 0.75631 | 2.4 | 1
2 x Vluchtdeur | -1 kelder | 0.2 | 1.05 | 2.35
4 x Vluchtdeur | -1 kelder | 0.1 | 1.05 | 2.35
2 x Vluchtdeur | -1 kelder | 0.25 | 2.35 | 1.05
4 x Vluchtdeur | 00 begane grond | 0.1 | 2.35 | 1.05
4 x Vluchtdeur | 00 begane grond | 3.048 | 2.35 | 1.05
Vluchtdeur | 00 begane grond | 0.25 | 2.35 | 1.05
4 x Vluchtdeur | 00 begane grond | 0.25 | 1.95 | 2.35
Vluchtdeur | 00 begane grond | 0.25 | 2.35 | 1.95
2 x Brandweerlift | 00 begane grond | 0.75631 | 2.4 | 1
Vluchtdeur | 00 begane grond | 0.1 | 2.35 | 1.95
4 x Vluchtdeur | 00 begane grond | 0.3 | 1.965 | 2.35
2 x Vluchtdeur | 00 begane grond | 3.048 | 2.35 | 1.965
2 x Vluchtdeur | 00 begane grond | 0.3 | 1.05 | 2.35
23 x Binnendeur | 02 tweede verdieping | 0.1 | 2.35 | 1.05
16 x Binnendeur | 02 tweede verdieping | 0.1 | 1.05 | 2.35
23 x Binnendeur | 03 derde verdieping | 0.1 | 2.35 | 1.05
16 x Binnendeur | 03 derde verdieping | 0.1 | 1.05 | 2.35
23 x Binnendeur | 04 vierde verdieping | 0.1 | 2.35 | 1.05
16 x Binnendeur | 04 vierde verdieping | 0.1 | 1.05 | 2.35
23 x Binnendeur | 05 vijfde verdieping | 0.1 | 2.35 | 1.05
16 x Binnendeur | 05 vijfde verdieping | 0.1 | 1.05 | 2.35
23 x Binnendeur | 06 zesde verdieping | 0.1 | 2.35 | 1.05
16 x Binnendeur | 06 zesde verdieping | 0.1 | 1.05 | 2.35
23 x Binnendeur | 07 zevende verdieping | 0.1 | 2.35 | 1.05
16 x Binnendeur | 07 zevende verdieping | 0.1 | 1.05 | 2.35
23 x Binnendeur | 08 achtste verdieping | 0.1 | 2.35 | 1.05
16 x Binnendeur | 08 achtste verdieping | 0.1 | 1.05 | 2.35
3 x Woningtoegangsdeur | 00 begane grond | 0.3 | 2.35 | 1.05
Woningtoegangsdeur | 00 begane grond | 3.048 | 2.35 | 1.05
30 x Binnendeur | 01 eerste verdieping | 0.1 | 2.35 | 1.05
19 x Binnendeur | 01 eerste verdieping | 0.1 | 1.05 | 2.35
8 x Binnendeur | 01 eerste verdieping | 3.048 | 2.35 | 1.05
3 x Binnendeur | 00 begane grond | 0.1 | 0.95 | 2.35
17 x Binnendeur | 00 begane grond | 0.1 | 2.35 | 1.05
5 x Binnendeur | 00 begane grond | 3.048 | 2.35 | 1.05
6 x Binnendeur | 00 begane grond | 0.1 | 1.05 | 2.35
2 x Binnendeur | 02 tweede verdieping | 3.048 | 2.35 | 1.05
2 x Binnendeur | 03 derde verdieping | 3.048 | 2.35 | 1.05
2 x Binnendeur | 04 vierde verdieping | 3.048 | 2.35 | 1.05
2 x Binnendeur | 05 vijfde verdieping | 3.048 | 2.35 | 1.05
2 x Binnendeur | 06 zesde verdieping | 3.048 | 2.35 | 1.05
2 x Binnendeur | 07 zevende verdieping | 3.048 | 2.35 | 1.05
2 x Binnendeur | 08 achtste verdieping | 3.048 | 2.35 | 1.05

# IfcSanitaryTerminal: NLRS_74_PF_UN_douche_gen:douchebak 900x900mm (49)
Type - Classification: 74.11 vaste sanitaire voorzieningen; standaard, sanitaire toestellen; normaal (NL-SfB); Material: <Unnamed>
Pset_EnvironmentalImpactIndicators - Reference: douchebak 900x900mm; sets with these values: 2
Name (NLRS_74_PF_UN_douche_gen:douchebak 900x900mm:...)
1530203
1530229
1530255
1530281
1530307
1530359
1530411
1557117
1557918
1557942
1560090
1560116
1560142
1560168
1560194
1560246
1560298
1565785
1565809
1565833
1565857
1565881
1565929
1565977
1600196
1600222
1600248
1600274
1600300
1600352
1600404
1605318
1605343
1605368
1605393
1605418
1605468
1605518
1609131
1609159
1609187
1609215
1609243
1609299
1609355
1668764
1668792
1668818
1668845

# IfcSanitaryTerminal: NLRS_74_PF_UN_toilet hangend_gen:toilet hangend (60)
Type - PredefinedType: TOILETPAN; Classification: 74.11 vaste sanitaire voorzieningen; standaard, sanitaire toestellen; normaal (NL-SfB); Material: <Unnamed>
Pset_EnvironmentalImpactIndicators - Reference: toilet hangend; sets with these values: 2
Name (NLRS_74_PF_UN_toilet hangend_gen:toilet hangend:...)
1530200
1530226
1530252
1530278
1530304
1530356
1530408
1557118
1557286
1557330
1557376
1557919
1557943
1560084
1560110
1560136
1560162
1560188
1560240
1560292
1565783
1565807
1565831
1565855
1565879
1565927
1565975
1600195
1600221
1600247
1600273
1600299
1600351
1600403
1605331
1605356
1605381
1605406
1605431
1605481
1605531
1609152
1609180
1609208
1609236
1609264
1609320
1609376
1668779
1668803
1668829
1668860
1733976
1733983
1733984
1733985
1741758
1741764
1741765
1741766

# IfcSanitaryTerminal: NLRS_74_PF_WB_wastafel_gen:wastafel (49)
Type - PredefinedType: SINK; Classification: 74.11 vaste sanitaire voorzieningen; standaard, sanitaire toestellen; normaal (NL-SfB); Material: <Unnamed>
Pset_EnvironmentalImpactIndicators - Reference: wastafel; sets with these values: 2
Name (NLRS_74_PF_WB_wastafel_gen:wastafel:...)
1530202
1530228
1530254
1530280
1530306
1530358
1530410
1557106
1557907
1557931
1560086
1560112
1560138
1560164
1560190
1560242
1560294
1565792
1565816
1565840
1565864
1565888
1565936
1565984
1600211
1600237
1600263
1600289
1600315
1600367
1600419
1605319
1605344
1605369
1605394
1605419
1605469
1605519
1609142
1609170
1609198
1609226
1609254
1609310
1609366
1668773
1668801
1668827
1668854

# IfcSlab: Floor:13_FL_funderingvloer 250mm, Funderingvloer
In: -1 kelder
Type - PredefinedType: FLOOR; Material: beton_gewapend_ihw
Type - Pset_ReinforcementBarPitchOfSlab - Description: Funderingvloer
Type - Pset_SlabCommon - LoadBearing: yes
Classification: 13.20 vloeren op grondslag; constructief, algemeen (verzamelniveau) (NL-SfB)
Pset_EnvironmentalImpactIndicators - Reference: 13_FL_funderingvloer 250mm; sets with these values: 2
Pset_SlabCommon - IsExternal: no; LoadBearing: no; PitchAngle: 0 deg; Reference: 13_FL_funderingvloer 250mm
Qto_SlabBaseQuantities - Width: 10.3 m; Length: 7.5 m; Depth: 0.25 m; Perimeter: 116.798 m; GrossArea: 77.25 m2; NetArea: 67.625 m2; GrossVolume: 19.3125 m3; NetVolume: 16.9063 m3

# IfcSlab: Floor:23_FL_skelet_balkon 200mm (42)
Type - PredefinedType: FLOOR; Material: beton_gewapend_prefab-element
Type - Pset_ReinforcementBarPitchOfSlab - Description: Balkonvloer
Type - Pset_SlabCommon - LoadBearing: no
Classification: 23.10 vloeren; niet constructief, algemeen (verzamelniveau) (NL-SfB)
Pset_EnvironmentalImpactIndicators - Reference: 23_FL_skelet_balkon 200mm; sets with these values: 2
Pset_SlabCommon - PitchAngle: 0 deg; IsExternal: yes; Reference: 23_FL_skelet_balkon 200mm
Qto_SlabBaseQuantities - Width: 2 m; Length: 3.5 m; Depth: 0.2 m; Perimeter: 36.0892 m; GrossArea: 7 m2; NetArea: 7 m2; GrossVolume: 1.4 m3; NetVolume: 1.4 m3
Name | In
6 x Balkonvloer | 03 derde verdieping
6 x Balkonvloer | 04 vierde verdieping
6 x Balkonvloer | 05 vijfde verdieping
6 x Balkonvloer | 06 zesde verdieping
6 x Balkonvloer | 07 zevende verdieping
6 x Balkonvloer | 08 achtste verdieping
6 x Balkonvloer | 02 tweede verdieping

# IfcSlab: Floor:28_FL_skelet_dakterrasvloer 250mm (6)
Type - PredefinedType: ROOF; Material: beton_gewapend_ihw
Type - Pset_ReinforcementBarPitchOfSlab - Description: Begaanbare dakvloer
Type - Pset_SlabCommon - LoadBearing: yes
Classification: 27.10 daken; niet constructief, algemeen (verzamelniveau) (NL-SfB)
Pset_EnvironmentalImpactIndicators - Reference: 28_FL_skelet_dakterrasvloer 250mm; sets with these values: 2
Pset_SlabCommon - IsExternal: no; LoadBearing: no; PitchAngle: 0 deg; Reference: 28_FL_skelet_dakterrasvloer 250mm
Qto_SlabBaseQuantities - Depth: 0.25 m
Name | In | Width (m) | Length (m) | Perimeter (m) | GrossArea (m2) = NetArea (m2) | GrossVolume (m3) = NetVolume (m3)
4 x Begaanbare dakvloer | 01 eerste verdieping | 2 | 2.4 | 28.8714 | 4.8 | 1.2
2 x Begaanbare dakvloer | 02 tweede verdieping | 22.75 | 4.625 | 179.626 | 105.219 | 26.3047

# IfcSlab: Floor:28_FL_skelet_dakvloer 250mm, Dakvloer
In: 09 negende verdieping
Type - PredefinedType: ROOF; Material: beton_gewapend_ihw
Type - Pset_ReinforcementBarPitchOfSlab - Description: Dakvloer
Type - Pset_SlabCommon - LoadBearing: yes
Classification: 27.10 daken; niet constructief, algemeen (verzamelniveau) (NL-SfB)
Pset_EnvironmentalImpactIndicators - Reference: 28_FL_skelet_dakvloer 250mm; sets with these values: 2
Pset_SlabCommon - IsExternal: no; LoadBearing: no; PitchAngle: 0 deg; Reference: 28_FL_skelet_dakvloer 250mm
Qto_SlabBaseQuantities - Width: 22.75 m; Length: 24.1 m; Depth: 0.25 m; Perimeter: 307.415 m; GrossArea: 548.275 m2; NetArea: 538.65 m2; GrossVolume: 137.069 m3; NetVolume: 134.662 m3

# IfcSlab: Floor:28_FL_skelet_vloer 250mm (9)
Type - PredefinedType: FLOOR; Material: beton_gewapend_ihw
Type - Pset_ReinforcementBarPitchOfSlab - Description: Constructieve vloer
Type - Pset_SlabCommon - LoadBearing: yes
Classification: 28.20 hoofddraagconstructies; wanden en vloeren, algemeen (verzamelniveau) (NL-SfB)
Pset_EnvironmentalImpactIndicators - Reference: 28_FL_skelet_vloer 250mm; sets with these values: 2
Pset_SlabCommon - IsExternal: no; LoadBearing: no; Reference: 28_FL_skelet_vloer 250mm; PitchAngle: 0 deg
Qto_SlabBaseQuantities - Depth: 0.25 m
Name | In | Width (m) | Length (m) | Perimeter (m) | GrossArea (m2) | NetArea (m2) | GrossVolume (m3) | NetVolume (m3)
Constructieve vloer | 02 tweede verdieping | 22.75 | 24.1 | 307.415 | 548.275 | 528.706 | 137.069 | 132.176
Constructieve vloer | 03 derde verdieping | 22.75 | 24.1 | 307.415 | 548.275 | 528.706 | 137.069 | 132.176
Constructieve vloer | 04 vierde verdieping | 22.75 | 24.1 | 307.415 | 548.275 | 528.706 | 137.069 | 132.176
Constructieve vloer | 05 vijfde verdieping | 22.75 | 24.1 | 307.415 | 548.275 | 528.706 | 137.069 | 132.176
Constructieve vloer | 06 zesde verdieping | 22.75 | 24.1 | 307.415 | 548.275 | 528.706 | 137.069 | 132.176
Constructieve vloer | 07 zevende verdieping | 22.75 | 24.1 | 307.415 | 548.275 | 528.706 | 137.069 | 132.176
Constructieve vloer | 01 eerste verdieping |  |  | 431.102 | 724.602 | 688.88 | 181.151 | 172.22
Constructieve vloer | 08 achtste verdieping | 22.75 | 24.1 | 307.415 | 548.275 | 528.706 | 137.069 | 132.176
Constructieve vloer | 00 begane grond |  |  | 379.921 | 745.662 | 728.117 | 186.416 | 182.029

# IfcSlab: Monolithic Landing:NLRS_24_STRL_bordes-beton prefab-300mm_gen_rsf (2)
In: 00 begane grond
Type - PredefinedType: LANDING
Type - Pset_ReinforcementBarPitchOfSlab - Description: Bordeselement
Classification: 24.15 trappen en hellingen; trappen, bordessen (NL-SfB); Material: beton_gewapend_prefab-element
Pset_EnvironmentalImpactIndicators - Reference: NLRS_24_STRL_bordes-beton prefab-300mm_gen_rsf; sets with these values: 2
Pset_SlabCommon - IsExternal: no; PitchAngle: 0 deg; Reference: NLRS_24_STRL_bordes-beton prefab-300mm_gen_rsf
Qto_SlabBaseQuantities - NetVolume: 0.460357 m3
Name
Hoofdtrap Landing 1
Hoofdtrap Landing 2

# IfcStair: Trap, Hoofdtrap
In: 00 begane grond
Type - PredefinedType: DOUBLE_RETURN_STAIR
Type - Pset_StairCommon - IsExternal: no; NosingLength: 0 m; NumberOfRiser: 0; NumberOfTreads: 0
Type - Pset_StairFlightCommon - NosingLength: 0 m; NumberOfRiser: 0; NumberOfTreads: 0
Classification: 24.10 trappen en hellingen; trappen, algemeen (verzamelniveau) (NL-SfB)
Pset_EnvironmentalImpactIndicators - Reference: NLRS_24_STR_reguliere trap-woonfunctie-breedte 1200mm_gen
Pset_StairCommon - Reference: NLRS_24_STR_reguliere trap-woonfunctie-breedte 1200mm_gen; NumberOfRiser: 21; NumberOfTreads: 21; RiserHeight: 0.185714 m; TreadLength: 0.22 m; WalkingLineOffset: 1.9685 m; TreadLengthAtOffset: 0.22 m; TreadLengthAtInnerSide: 0.22 m
Pset_StairFlightCommon - Reference: NLRS_24_STR_reguliere trap-woonfunctie-breedte 1200mm_gen; NumberOfRiser: 21; NumberOfTreads: 21; RiserHeight: 0.185714 m; TreadLength: 0.22 m; WalkingLineOffset: 1.9685 m; TreadLengthAtOffset: 0.22 m; TreadLengthAtInnerSide: 0.22 m

# IfcStair: Trap (18)
Type - PredefinedType: STRAIGHT_RUN_STAIR
Type - Pset_StairCommon - IsExternal: no; NosingLength: 0 m; NumberOfRiser: 0; NumberOfTreads: 0
Type - Pset_StairFlightCommon - NosingLength: 0 m; NumberOfRiser: 0; NumberOfTreads: 0
Classification: 24.10 trappen en hellingen; trappen, algemeen (verzamelniveau) (NL-SfB)
Pset_EnvironmentalImpactIndicators - Reference: NLRS_24_STR_reguliere trap-woonfunctie-breedte 1200mm_gen
Pset_StairCommon - Reference: NLRS_24_STR_reguliere trap-woonfunctie-breedte 1200mm_gen; TreadLength: 0.22 m; WalkingLineOffset: 1.9685 m; TreadLengthAtOffset: 0.22 m; TreadLengthAtInnerSide: 0.22 m
Pset_StairFlightCommon - Reference: NLRS_24_STR_reguliere trap-woonfunctie-breedte 1200mm_gen; TreadLength: 0.22 m; WalkingLineOffset: 1.9685 m; TreadLengthAtOffset: 0.22 m; TreadLengthAtInnerSide: 0.22 m
Name | In | Pset_StairCommon, NumberOfRiser = Pset_StairCommon, NumberOfTreads = Pset_StairFlightCommon, NumberOfRiser = Pset_StairFlightCommon, NumberOfTreads | Pset_StairCommon, RiserHeight (m) = Pset_StairFlightCommon, RiserHeight (m)
2 x Hoofdtrap | 02 tweede verdieping | 16 | 0.1875
2 x Hoofdtrap | 03 derde verdieping | 16 | 0.1875
2 x Hoofdtrap | 04 vierde verdieping | 16 | 0.1875
2 x Hoofdtrap | 05 vijfde verdieping | 16 | 0.1875
2 x Hoofdtrap | 06 zesde verdieping | 16 | 0.1875
2 x Hoofdtrap | 07 zevende verdieping | 16 | 0.1875
2 x Hoofdtrap | 01 eerste verdieping | 16 | 0.1875
2 x Hoofdtrap | -1 kelder | 16 | 0.188235
2 x Hoofdtrap | 00 begane grond | 21 | 0.185714

# IfcStairFlight: Monolithic Run:NLRS_24_STRR_trap-beton prefab-monolithisch-recht_gen_rsf (21)
Type - PredefinedType: STRAIGHT
Type - Pset_StairFlightCommon - NosingLength: 0 m
Classification: 24.10 trappen en hellingen; trappen, algemeen (verzamelniveau) (NL-SfB); Material: beton_gewapend_prefab-element
Pset_EnvironmentalImpactIndicators - Reference: NLRS_24_STRR_trap-beton prefab-monolithisch-recht_gen_rsf
Pset_StairFlightCommon - Reference: NLRS_24_STRR_trap-beton prefab-monolithisch-recht_gen_rsf; TreadLength: 0.22 m; WalkingLineOffset: 1.9685 m; TreadLengthAtOffset: 0.22 m; TreadLengthAtInnerSide: 0.22 m
Name | In | NumberOfRiser = NumberOfTreads | RiserHeight (m) | Length (m) | NetVolume (m3)
2 x Hoofdtrap Run 1 | 02 tweede verdieping | 16 | 0.1875 | 3.52 | 1.20115
2 x Hoofdtrap Run 1 | 03 derde verdieping | 16 | 0.1875 | 3.52 | 1.20115
2 x Hoofdtrap Run 1 | 04 vierde verdieping | 16 | 0.1875 | 3.52 | 1.20115
2 x Hoofdtrap Run 1 | 05 vijfde verdieping | 16 | 0.1875 | 3.52 | 1.20115
2 x Hoofdtrap Run 1 | 06 zesde verdieping | 16 | 0.1875 | 3.52 | 1.20115
2 x Hoofdtrap Run 1 | 07 zevende verdieping | 16 | 0.1875 | 3.52 | 1.20115
2 x Hoofdtrap Run 1 | 01 eerste verdieping | 16 | 0.1875 | 3.52 | 1.20115
2 x Hoofdtrap Run 1 | -1 kelder | 16 | 0.188235 | 3.52 | 1.20409
2 x Hoofdtrap Run 1 | 00 begane grond | 21 | 0.185714 | 4.62 | 1.5757
Hoofdtrap Run 1 | 00 begane grond | 8 | 0.185714 | 1.76 | 0.590954
Hoofdtrap Run 2 | 00 begane grond | 5 | 0.185714 | 1.1 | 0.38933
Hoofdtrap Run 3 | 00 begane grond | 8 | 0.185714 | 1.76 | 0.610699

# IfcWall: Basic Wall:21_WA_gevel_binnenspouwwand 100mm_gen (54)
Type - PredefinedType: STANDARD
Type - Pset_ReinforcementBarPitchOfWall - Description: Binnenspouwblad
Type - Pset_WallCommon - LoadBearing: no
Classification: 21.12 buitenwanden; niet constructief, spouwwanden (NL-SfB); Material: ntb_ntb_ntb
Qto_WallBaseQuantities - Length: 7.25 m; Width: 0.1 m; GrossFootprintArea: 0.725 m2
Pset_EnvironmentalImpactIndicators - Reference: 21_WA_gevel_binnenspouwwand 100mm_gen; sets with these values: 2
Pset_WallCommon - ExtendToStructure: no; Reference: 21_WA_gevel_binnenspouwwand 100mm_gen; IsExternal: yes
Name | In | Height (m) | GrossVolume (m3) = NetVolume (m3) | GrossSideArea (m2) = NetSideArea (m2)
6 x Binnenspouwblad | 02 tweede verdieping | 2.75 | 1.99375 | 19.9375
6 x Binnenspouwblad | 03 derde verdieping | 2.75 | 1.99375 | 19.9375
6 x Binnenspouwblad | 04 vierde verdieping | 2.75 | 1.99375 | 19.9375
6 x Binnenspouwblad | 05 vijfde verdieping | 2.75 | 1.99375 | 19.9375
6 x Binnenspouwblad | 06 zesde verdieping | 2.75 | 1.99375 | 19.9375
6 x Binnenspouwblad | 07 zevende verdieping | 2.75 | 1.99375 | 19.9375
6 x Binnenspouwblad | 01 eerste verdieping | 2.75 | 1.99375 | 19.9375
6 x Binnenspouwblad | 08 achtste verdieping | 2.75 | 1.99375 | 19.9375
3 x Binnenspouwblad | 00 begane grond | 3.65 | 2.64625 | 26.4625
3 x Binnenspouwblad | 00 begane grond | 3.65 | 2.3995 | 23.995

# IfcWall: Basic Wall:21_WA_gevel_buitenwand 100mm_gen (4)
In: 01 eerste verdieping
Type - PredefinedType: STANDARD
Type - Pset_ReinforcementBarPitchOfWall - Description: Gevelwand
Type - Pset_WallCommon - LoadBearing: no
Classification: 21.10 buitenwanden; niet constructief, algemeen (verzamelniveau) (NL-SfB); Material: ntb_ntb_ntb
Qto_WallBaseQuantities - Height: 3 m; Length: 2.4 m; Width: 0.1 m; GrossFootprintArea: 0.24 m2; GrossVolume: 0.72 m3; GrossSideArea: 7.2 m2; NetSideArea: 7.2 m2; NetVolume: 0.72 m3
Pset_EnvironmentalImpactIndicators - Reference: 21_WA_gevel_buitenwand 100mm_gen; sets with these values: 2
Pset_WallCommon - ExtendToStructure: no; IsExternal: yes; Reference: 21_WA_gevel_buitenwand 100mm_gen
MiniBIM ILS - BouwwerkNummer: 02; Gebruiksbestemming: Woonfunctie; Glaspercentage: 40
Name | Orientatie
2 x Gevelwand | Oost
2 x Gevelwand | West

# IfcWall: Basic Wall:21_WA_gevel_buitenwand 150mm_gen (12)
In: 01 eerste verdieping
Type - PredefinedType: STANDARD
Type - Pset_ReinforcementBarPitchOfWall - Description: Gevelwand
Type - Pset_WallCommon - LoadBearing: no
Classification: 21.10 buitenwanden; niet constructief, algemeen (verzamelniveau) (NL-SfB); Material: ntb_ntb_ntb
Qto_WallBaseQuantities - Height: 2.75 m; Width: 0.15 m
Pset_EnvironmentalImpactIndicators - Reference: 21_WA_gevel_buitenwand 150mm_gen; sets with these values: 2
Pset_WallCommon - ExtendToStructure: no; IsExternal: yes; Reference: 21_WA_gevel_buitenwand 150mm_gen
MiniBIM ILS - BouwwerkNummer: 02; Gebruiksbestemming: Woonfunctie; Glaspercentage: 40
Name | Length (m) | GrossFootprintArea (m2) | GrossVolume (m3) | GrossSideArea (m2) = NetSideArea (m2) | NetVolume (m3) | Orientatie
2 x Gevelwand | 1.95 | 0.2925 | 0.804375 | 5.3625 | 0.804375 | Noord
2 x Gevelwand | 2.55 | 0.3825 | 1.05187 | 7.0125 | 1.05187 | Oost
2 x Gevelwand | 1.8 | 0.27 | 0.7425 | 4.95 | 0.7425 | Zuid
2 x Gevelwand | 1.95 | 0.2925 | 0.804375 | 5.3625 | 0.804375 | Zuid
2 x Gevelwand | 1.8 | 0.27 | 0.7425 | 4.95 | 0.7425 | Noord
2 x Gevelwand | 2.55 | 0.3825 | 1.05187 | 7.0125 | 1.05188 | West

# IfcWall: Basic Wall:21_WA_gevel_buitenwand 300mm_gen (82)
Type - PredefinedType: STANDARD
Type - Pset_ReinforcementBarPitchOfWall - Description: Gevelwand
Type - Pset_WallCommon - LoadBearing: no
Classification: 21.10 buitenwanden; niet constructief, algemeen (verzamelniveau) (NL-SfB); Material: ntb_ntb_ntb
Qto_WallBaseQuantities - Width: 0.3 m
Pset_EnvironmentalImpactIndicators - Reference: 21_WA_gevel_buitenwand 300mm_gen; sets with these values: 2
Pset_WallCommon - ExtendToStructure: no; IsExternal: yes; Reference: 21_WA_gevel_buitenwand 300mm_gen
Name | In | Height (m) | Length (m) | GrossFootprintArea (m2) | GrossVolume (m3) | GrossSideArea (m2) | NetSideArea (m2) | NetVolume (m3) | BouwwerkNummer | Gebruiksbestemming | Glaspercentage | Orientatie
Gevelwand | 02 tweede verdieping | 3 | 24.1 | 7.23 | 21.69 | 72.3 | 72.3 | 21.69 | 01 | Woonfunctie | 40 | Oost
Gevelwand | 02 tweede verdieping | 3 | 23.35 | 7.005 | 21.015 | 70.05 | 70.05 | 21.015 | 02 | Woonfunctie | 40 | Zuid
Gevelwand | 02 tweede verdieping | 3 | 24.1 | 7.23 | 21.69 | 72.3 | 72.3 | 21.69 | 02 | Woonfunctie | 40 | West
Gevelwand | 02 tweede verdieping | 3 | 23.35 | 7.005 | 21.015 | 70.05 | 70.05 | 21.015 | 01 | Woonfunctie | 40 | Noord
Gevelwand | 03 derde verdieping | 3 | 24.1 | 7.23 | 21.69 | 72.3 | 72.3 | 21.69 | 01 | Woonfunctie | 40 | Oost
Gevelwand | 03 derde verdieping | 3 | 23.35 | 7.005 | 21.015 | 70.05 | 70.05 | 21.015 | 02 | Woonfunctie | 40 | Zuid
Gevelwand | 03 derde verdieping | 3 | 24.1 | 7.23 | 21.69 | 72.3 | 72.3 | 21.69 | 02 | Woonfunctie | 40 | West
Gevelwand | 03 derde verdieping | 3 | 23.35 | 7.005 | 21.015 | 70.05 | 70.05 | 21.015 | 01 | Woonfunctie | 40 | Noord
Gevelwand | 04 vierde verdieping | 3 | 24.1 | 7.23 | 21.69 | 72.3 | 72.3 | 21.69 | 01 | Woonfunctie | 40 | Oost
Gevelwand | 04 vierde verdieping | 3 | 23.35 | 7.005 | 21.015 | 70.05 | 70.05 | 21.015 | 02 | Woonfunctie | 40 | Zuid
Gevelwand | 04 vierde verdieping | 3 | 24.1 | 7.23 | 21.69 | 72.3 | 72.3 | 21.69 | 02 | Woonfunctie | 40 | West
Gevelwand | 04 vierde verdieping | 3 | 23.35 | 7.005 | 21.015 | 70.05 | 70.05 | 21.015 | 01 | Woonfunctie | 40 | Noord
Gevelwand | 05 vijfde verdieping | 3 | 24.1 | 7.23 | 21.69 | 72.3 | 72.3 | 21.69 | 01 | Woonfunctie | 40 | Oost
Gevelwand | 05 vijfde verdieping | 3 | 23.35 | 7.005 | 21.015 | 70.05 | 70.05 | 21.015 | 02 | Woonfunctie | 40 | Zuid
Gevelwand | 05 vijfde verdieping | 3 | 24.1 | 7.23 | 21.69 | 72.3 | 72.3 | 21.69 | 02 | Woonfunctie | 40 | West
Gevelwand | 05 vijfde verdieping | 3 | 23.35 | 7.005 | 21.015 | 70.05 | 70.05 | 21.015 | 01 | Woonfunctie | 40 | Noord
Gevelwand | 06 zesde verdieping | 3 | 24.1 | 7.23 | 21.69 | 72.3 | 72.3 | 21.69 | 01 | Woonfunctie | 40 | Oost
Gevelwand | 06 zesde verdieping | 3 | 23.35 | 7.005 | 21.015 | 70.05 | 70.05 | 21.015 | 02 | Woonfunctie | 40 | Zuid
Gevelwand | 06 zesde verdieping | 3 | 24.1 | 7.23 | 21.69 | 72.3 | 72.3 | 21.69 | 02 | Woonfunctie | 40 | West
Gevelwand | 06 zesde verdieping | 3 | 23.35 | 7.005 | 21.015 | 70.05 | 70.05 | 21.015 | 01 | Woonfunctie | 40 | Noord
Gevelwand | 07 zevende verdieping | 3 | 24.1 | 7.23 | 21.69 | 72.3 | 72.3 | 21.69 | 01 | Woonfunctie | 40 | Oost
Gevelwand | 07 zevende verdieping | 3 | 23.35 | 7.005 | 21.015 | 70.05 | 70.05 | 21.015 | 02 | Woonfunctie | 40 | Zuid
Gevelwand | 07 zevende verdieping | 3 | 24.1 | 7.23 | 21.69 | 72.3 | 72.3 | 21.69 | 02 | Woonfunctie | 40 | West
Gevelwand | 07 zevende verdieping | 3 | 23.35 | 7.005 | 21.015 | 70.05 | 70.05 | 21.015 | 01 | Woonfunctie | 40 | Noord
Gevelwand | 01 eerste verdieping | 3 | 6.775 | 2.0325 | 6.0975 | 20.325 | 20.325 | 6.0975 | 02 | Bijeenkomstfunctie | 60 | Oost
Gevelwand | 01 eerste verdieping | 3 | 23.35 | 7.005 | 21.015 | 70.05 | 70.05 | 21.015 | 02 | Bijeenkomstfunctie | 60 | Zuid
Gevelwand | 08 achtste verdieping | 3 | 24.1 | 7.23 | 21.69 | 72.3 | 72.3 | 21.69 | 01 | Woonfunctie | 40 | Oost
Gevelwand | 08 achtste verdieping | 3 | 23.35 | 7.005 | 21.015 | 70.05 | 70.05 | 21.015 | 02 | Woonfunctie | 40 | Zuid
Gevelwand | 08 achtste verdieping | 3 | 24.1 | 7.23 | 21.69 | 72.3 | 72.3 | 21.69 | 02 | Woonfunctie | 40 | West
Gevelwand | 08 achtste verdieping | 3 | 23.35 | 7.005 | 21.015 | 70.05 | 70.05 | 21.015 | 01 | Woonfunctie | 40 | Noord
Gevelwand | 09 negende verdieping | 0.7 | 24.1 | 7.23 | 5.061 | 16.87 | 16.87 | 5.061 | 02 | Woonfunctie | 40 | Oost
Gevelwand | 09 negende verdieping | 0.7 | 23.35 | 7.005 | 4.9035 | 16.345 | 16.345 | 4.9035 | 02 | Woonfunctie | 40 | Zuid
Gevelwand | 09 negende verdieping | 0.7 | 24.1 | 7.23 | 5.061 | 16.87 | 16.87 | 5.061 | 02 | Woonfunctie | 40 | West
Gevelwand | 09 negende verdieping | 0.7 | 23.35 | 7.005 | 4.9035 | 16.345 | 16.345 | 4.9035 | 02 | Woonfunctie | 40 | Noord
Gevelwand | 01 eerste verdieping | 3 | 6.65 | 1.995 | 5.985 | 19.95 | 19.95 | 5.985 | 02 | Woonfunctie | 40 | Oost
Gevelwand | 01 eerste verdieping | 3 | 10.95 | 3.285 | 9.855 | 32.85 | 32.85 | 9.855 | 02 | Woonfunctie | 40 | Oost
Gevelwand | 01 eerste verdieping | 3 | 6.775 | 2.0325 | 6.0975 | 20.325 | 20.325 | 6.0975 | 02 | Bijeenkomstfunctie | 60 | West
Gevelwand | 01 eerste verdieping | 3 | 6.65 | 1.995 | 5.985 | 19.95 | 19.95 | 5.985 | 02 | Woonfunctie | 40 | West
Gevelwand | 01 eerste verdieping | 3 | 10.95 | 3.285 | 9.855 | 32.85 | 32.85 | 9.855 | 02 | Woonfunctie | 40 | West
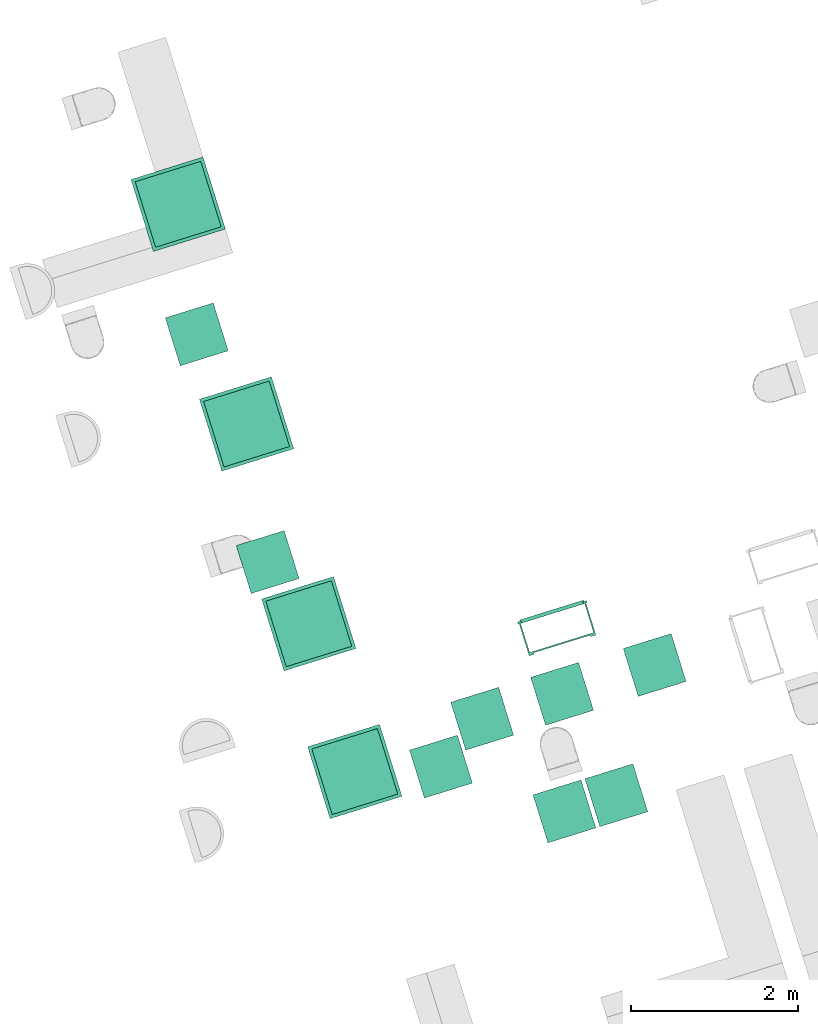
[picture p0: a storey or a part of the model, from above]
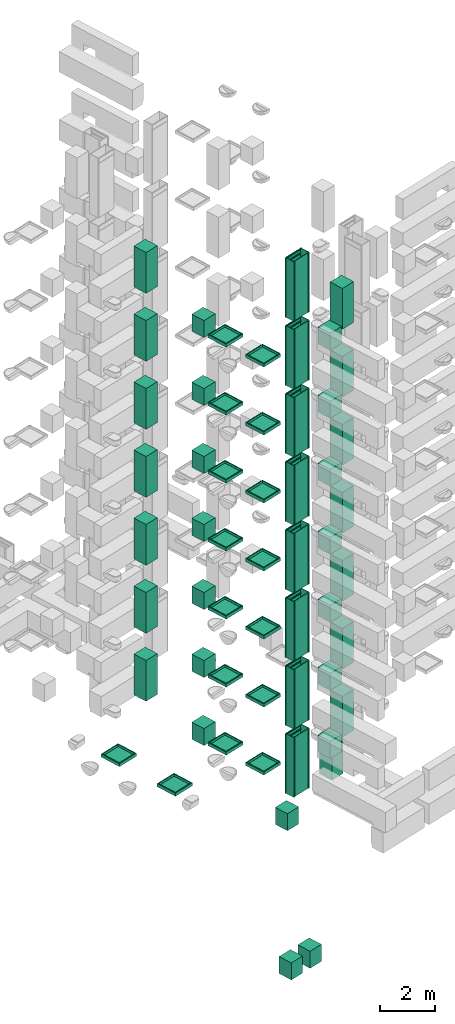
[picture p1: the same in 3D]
Properties of the parts of a building model (IFC4), part 2 of 2

# IfcWall: Basic Wall:21_WA_gevel_buitenwand 300mm_gen (82)
Name | In | Height (m) | Length (m) | GrossFootprintArea (m2) | GrossVolume (m3) | GrossSideArea (m2) | NetSideArea (m2) | NetVolume (m3) | BouwwerkNummer | Gebruiksbestemming | Glaspercentage | Orientatie
Gevelwand | 00 begane grond | 4.4 | 11.525 |  | 15.1843 | 50.71 | 50.71 | 15.1843 | 02 | Bijeenkomstfunctie | 60 | Oost
Gevelwand | 00 begane grond | 4.4 | 23.35 | 7.005 | 30.822 | 102.74 | 102.74 | 30.822 | 02 | Bijeenkomstfunctie | 60 | Zuid
Gevelwand | 00 begane grond | 3.9 | 6.775 | 2.0325 | 7.92675 | 26.4225 | 26.4225 | 7.92675 | 02 | Woonfunctie | 40 | West
Gevelwand | 02 tweede verdieping | 0.7 | 4.325 | 1.2975 | 0.90825 | 3.0275 | 3.0275 | 0.90825 | 02 | Bijeenkomstfunctie | 0 | West
Gevelwand | 02 tweede verdieping | 0.7 | 23.35 | 7.005 | 4.9035 | 16.345 | 16.345 | 4.9035 | 02 | Bijeenkomstfunctie | 0 | Zuid
Gevelwand | 02 tweede verdieping | 0.7 | 4.325 | 1.2975 | 0.90825 | 3.0275 | 3.0275 | 0.90825 | 02 | Bijeenkomstfunctie | 0 | Oost
Gevelwand | 02 tweede verdieping | 0.7 | 4.325 | 1.2975 | 0.90825 | 3.0275 | 3.0275 | 0.90825 | 02 | Woonfunctie | 0 | West
Gevelwand | 02 tweede verdieping | 0.7 | 23.35 | 7.005 | 4.9035 | 16.345 | 16.345 | 4.9035 | 02 | Woonfunctie | 0 | Noord
Gevelwand | 02 tweede verdieping | 0.7 | 4.325 | 1.2975 | 0.90825 | 3.0275 | 3.0275 | 0.90825 | 02 | Woonfunctie | 0 | Oost
Gevelwand | 00 begane grond | 3.9 | 4.75 |  | 4.7885 | 16.0575 | 16.0575 | 4.7885 | 02 | Overige gebruiksfunctie | 10 | West
Gevelwand | 00 begane grond | 3.9 | 10.3 | 3.09 | 10.6657 | 35.5522 | 35.5522 | 10.6657 | 02 | Bijeenkomstfunctie | 80 | West
Gevelwand | 00 begane grond | 3.9 | 11.525 |  | 10.6849 | 35.712 | 35.712 | 10.6849 | 02 | Bijeenkomstfunctie | 60 | West
Gevelwand | 00 begane grond | 4.4 | 10.3 | 3.09 | 13.596 | 45.32 | 40.7023 | 12.2107 | 02 | Woonfunctie | 80 | Oost
Gevelwand | 00 begane grond | 4.4 | 4.75 |  | 5.501 | 18.4325 | 18.4325 | 5.501 | 02 | Overige gebruiksfunctie | 10 | Oost
Gevelwand | 00 begane grond | 4.4 | 6.775 | 2.0325 | 8.943 | 29.81 | 29.81 | 8.943 | 02 | Woonfunctie | 40 | Oost
4 x Gevelwand | 01 eerste verdieping | 3 | 0.85 | 0.255 | 0.765 | 2.55 | 2.55 | 0.765 | 01 | Woonfunctie | 40 | Noord
3 x Gevelwand | 01 eerste verdieping | 2.75 | 0.6 | 0.18 | 0.495 | 1.65 | 1.65 | 0.495 | 01 | Woonfunctie | 40 | Oost
3 x Gevelwand | 01 eerste verdieping | 2.75 | 0.6 | 0.18 | 0.495 | 1.65 | 1.65 | 0.495 | 01 | Woonfunctie | 40 | West
3 x Gevelwand | 01 eerste verdieping | 2.75 | 6.65 | 1.995 | 5.48625 | 18.2875 | 18.2875 | 5.48625 | 01 | Woonfunctie | 40 | Noord
4 x Gevelwand | 00 begane grond | 4.4 | 0.85 | 0.255 | 1.122 | 3.74 | 3.74 | 1.122 | 01 | Woonfunctie | 40 | Noord
3 x Gevelwand | 00 begane grond | 4.4 | 0.6 | 0.18 | 0.792 | 2.64 | 2.64 | 0.792 | 01 | Woonfunctie | 40 | Oost
3 x Gevelwand | 00 begane grond | 4.4 | 0.6 | 0.18 | 0.792 | 2.64 | 2.64 | 0.792 | 01 | Woonfunctie | 40 | West
3 x Gevelwand | 00 begane grond | 4.4 | 6.65 | 1.995 | 8.03775 | 26.7925 | 26.7925 | 8.03775 | 01 | Woonfunctie | 40 | Noord
Gevelwand | 01 eerste verdieping | 3 | 4.175 | 1.2525 | 3.7575 | 12.525 | 12.525 | 3.7575 | 02 | Woonfunctie | 40 | West
Gevelwand | 01 eerste verdieping | 3 | 4.175 | 1.2525 | 3.7575 | 12.525 | 12.525 | 3.7575 | 02 | Woonfunctie | 40 | Oost

# IfcWall: Basic Wall:22_WA_afbouw_binnenwand 100mm_gen (567)
Type - PredefinedType: STANDARD
Type - Pset_ReinforcementBarPitchOfWall - Description: Binnenwand
Type - Pset_WallCommon - LoadBearing: no
Classification: 22.10 binnenwanden; niet constructief, algemeen (verzamelniveau) (NL-SfB); Material: ntb_ntb_ntb
Qto_WallBaseQuantities - Width: 0.1 m
Pset_EnvironmentalImpactIndicators - Reference: 22_WA_afbouw_binnenwand 100mm_gen; sets with these values: 2
Pset_WallCommon - IsExternal: no; ExtendToStructure: no; Reference: 22_WA_afbouw_binnenwand 100mm_gen
Name | In | Height (m) | Length (m) | GrossFootprintArea (m2) | GrossVolume (m3) = NetVolume (m3) | GrossSideArea (m2) = NetSideArea (m2)
Binnenwand | 02 tweede verdieping | 2.75 | 1.45 | 0.145 | 0.152 | 1.52
3 x Binnenwand | 02 tweede verdieping | 2.75 | 1.2 | 0.12 | 0.08325 | 0.8325
2 x Binnenwand | 02 tweede verdieping | 2.75 | 1.5 | 0.15 | 0.16575 | 1.6575
Binnenwand | 03 derde verdieping | 2.75 | 1.45 | 0.145 | 0.152 | 1.52
3 x Binnenwand | 03 derde verdieping | 2.75 | 1.2 | 0.12 | 0.08325 | 0.8325
2 x Binnenwand | 03 derde verdieping | 2.75 | 1.5 | 0.15 | 0.16575 | 1.6575
Binnenwand | 04 vierde verdieping | 2.75 | 1.45 | 0.145 | 0.152 | 1.52
3 x Binnenwand | 04 vierde verdieping | 2.75 | 1.2 | 0.12 | 0.08325 | 0.8325
2 x Binnenwand | 04 vierde verdieping | 2.75 | 1.5 | 0.15 | 0.16575 | 1.6575
Binnenwand | 05 vijfde verdieping | 2.75 | 1.45 | 0.145 | 0.152 | 1.52
3 x Binnenwand | 05 vijfde verdieping | 2.75 | 1.2 | 0.12 | 0.08325 | 0.8325
2 x Binnenwand | 05 vijfde verdieping | 2.75 | 1.5 | 0.15 | 0.16575 | 1.6575
Binnenwand | 06 zesde verdieping | 2.75 | 1.45 | 0.145 | 0.152 | 1.52
3 x Binnenwand | 06 zesde verdieping | 2.75 | 1.2 | 0.12 | 0.08325 | 0.8325
2 x Binnenwand | 06 zesde verdieping | 2.75 | 1.5 | 0.15 | 0.16575 | 1.6575
Binnenwand | 07 zevende verdieping | 2.75 | 1.45 | 0.145 | 0.152 | 1.52
3 x Binnenwand | 07 zevende verdieping | 2.75 | 1.2 | 0.12 | 0.08325 | 0.8325
2 x Binnenwand | 07 zevende verdieping | 2.75 | 1.5 | 0.15 | 0.16575 | 1.6575
Binnenwand | 01 eerste verdieping | 2.75 | 1.45 | 0.145 | 0.152 | 1.52
Binnenwand | 01 eerste verdieping | 2.75 | 1.2 | 0.12 | 0.08325 | 0.8325
2 x Binnenwand | 01 eerste verdieping | 2.75 | 1.5 | 0.15 | 0.16575 | 1.6575
Binnenwand | 08 achtste verdieping | 2.75 | 1.45 | 0.145 | 0.152 | 1.52
3 x Binnenwand | 08 achtste verdieping | 2.75 | 1.2 | 0.12 | 0.08325 | 0.8325
2 x Binnenwand | 08 achtste verdieping | 2.75 | 1.5 | 0.15 | 0.16575 | 1.6575
2 x Binnenwand | -1 kelder | 2.95 | 2.7 | 0.27 | 0.7965 | 7.965
2 x Binnenwand | -1 kelder | 2.95 | 3.265 | 0.3265 | 0.469675 | 4.69675
2 x Binnenwand | 00 begane grond | 3.65 | 1.2 | 0.12 | 0.19125 | 1.9125
Binnenwand | 00 begane grond | 3.65 | 7.25 | 0.725 | 2.188 | 21.88
2 x Binnenwand | 00 begane grond | 3.65 | 1.01 | 0.101 | 0.36865 | 3.6865
2 x Binnenwand | 00 begane grond | 3.65 | 4.45 | 0.445 | 1.3775 | 13.775
Binnenwand | 02 tweede verdieping | 2.75 | 4.45 | 0.445 | 0.977 | 9.77
Binnenwand | 02 tweede verdieping | 2.75 | 3.1 | 0.31 | 0.60575 | 6.0575
2 x Binnenwand | 02 tweede verdieping | 2.75 | 1.25 | 0.125 | 0.097 | 0.97
2 x Binnenwand | 02 tweede verdieping | 2.75 | 1.15 | 0.115 | 0.31625 | 3.1625
5 x Binnenwand | 02 tweede verdieping | 2.75 | 1.25 | 0.125 | 0.34375 | 3.4375
4 x Binnenwand | 02 tweede verdieping | 2.75 | 0.85 | 0.085 | 0.23375 | 2.3375
2 x Binnenwand | 02 tweede verdieping | 2.75 | 2.5 | 0.25 | 0.44075 | 4.4075
2 x Binnenwand | 02 tweede verdieping | 2.75 | 6.675 | 0.6675 | 1.58888 | 15.8887
2 x Binnenwand | 02 tweede verdieping | 2.75 | 3.2 | 0.32 | 0.60575 | 6.0575
Binnenwand | 03 derde verdieping | 2.75 | 4.45 | 0.445 | 0.977 | 9.77
Binnenwand | 03 derde verdieping | 2.75 | 3.1 | 0.31 | 0.60575 | 6.0575
2 x Binnenwand | 03 derde verdieping | 2.75 | 1.25 | 0.125 | 0.097 | 0.97
2 x Binnenwand | 03 derde verdieping | 2.75 | 1.15 | 0.115 | 0.31625 | 3.1625
5 x Binnenwand | 03 derde verdieping | 2.75 | 1.25 | 0.125 | 0.34375 | 3.4375
4 x Binnenwand | 03 derde verdieping | 2.75 | 0.85 | 0.085 | 0.23375 | 2.3375
2 x Binnenwand | 03 derde verdieping | 2.75 | 2.5 | 0.25 | 0.44075 | 4.4075
2 x Binnenwand | 03 derde verdieping | 2.75 | 6.675 | 0.6675 | 1.58888 | 15.8887
2 x Binnenwand | 03 derde verdieping | 2.75 | 3.2 | 0.32 | 0.60575 | 6.0575
Binnenwand | 04 vierde verdieping | 2.75 | 4.45 | 0.445 | 0.977 | 9.77
Binnenwand | 04 vierde verdieping | 2.75 | 3.1 | 0.31 | 0.60575 | 6.0575
2 x Binnenwand | 04 vierde verdieping | 2.75 | 1.25 | 0.125 | 0.097 | 0.97
2 x Binnenwand | 04 vierde verdieping | 2.75 | 1.15 | 0.115 | 0.31625 | 3.1625
5 x Binnenwand | 04 vierde verdieping | 2.75 | 1.25 | 0.125 | 0.34375 | 3.4375
4 x Binnenwand | 04 vierde verdieping | 2.75 | 0.85 | 0.085 | 0.23375 | 2.3375
2 x Binnenwand | 04 vierde verdieping | 2.75 | 2.5 | 0.25 | 0.44075 | 4.4075
2 x Binnenwand | 04 vierde verdieping | 2.75 | 6.675 | 0.6675 | 1.58888 | 15.8887
2 x Binnenwand | 04 vierde verdieping | 2.75 | 3.2 | 0.32 | 0.60575 | 6.0575
Binnenwand | 05 vijfde verdieping | 2.75 | 4.45 | 0.445 | 0.977 | 9.77
Binnenwand | 05 vijfde verdieping | 2.75 | 3.1 | 0.31 | 0.60575 | 6.0575
2 x Binnenwand | 05 vijfde verdieping | 2.75 | 1.25 | 0.125 | 0.097 | 0.97
2 x Binnenwand | 05 vijfde verdieping | 2.75 | 1.15 | 0.115 | 0.31625 | 3.1625
5 x Binnenwand | 05 vijfde verdieping | 2.75 | 1.25 | 0.125 | 0.34375 | 3.4375
4 x Binnenwand | 05 vijfde verdieping | 2.75 | 0.85 | 0.085 | 0.23375 | 2.3375
2 x Binnenwand | 05 vijfde verdieping | 2.75 | 2.5 | 0.25 | 0.44075 | 4.4075
2 x Binnenwand | 05 vijfde verdieping | 2.75 | 6.675 | 0.6675 | 1.58888 | 15.8887
2 x Binnenwand | 05 vijfde verdieping | 2.75 | 3.2 | 0.32 | 0.60575 | 6.0575
Binnenwand | 06 zesde verdieping | 2.75 | 4.45 | 0.445 | 0.977 | 9.77
Binnenwand | 06 zesde verdieping | 2.75 | 3.1 | 0.31 | 0.60575 | 6.0575
2 x Binnenwand | 06 zesde verdieping | 2.75 | 1.25 | 0.125 | 0.097 | 0.97
2 x Binnenwand | 06 zesde verdieping | 2.75 | 1.15 | 0.115 | 0.31625 | 3.1625
5 x Binnenwand | 06 zesde verdieping | 2.75 | 1.25 | 0.125 | 0.34375 | 3.4375
4 x Binnenwand | 06 zesde verdieping | 2.75 | 0.85 | 0.085 | 0.23375 | 2.3375
2 x Binnenwand | 06 zesde verdieping | 2.75 | 2.5 | 0.25 | 0.44075 | 4.4075
2 x Binnenwand | 06 zesde verdieping | 2.75 | 6.675 | 0.6675 | 1.58888 | 15.8887
2 x Binnenwand | 06 zesde verdieping | 2.75 | 3.2 | 0.32 | 0.60575 | 6.0575
Binnenwand | 07 zevende verdieping | 2.75 | 4.45 | 0.445 | 0.977 | 9.77
Binnenwand | 07 zevende verdieping | 2.75 | 3.1 | 0.31 | 0.60575 | 6.0575
2 x Binnenwand | 07 zevende verdieping | 2.75 | 1.25 | 0.125 | 0.097 | 0.97
2 x Binnenwand | 07 zevende verdieping | 2.75 | 1.15 | 0.115 | 0.31625 | 3.1625
5 x Binnenwand | 07 zevende verdieping | 2.75 | 1.25 | 0.125 | 0.34375 | 3.4375
4 x Binnenwand | 07 zevende verdieping | 2.75 | 0.85 | 0.085 | 0.23375 | 2.3375
2 x Binnenwand | 07 zevende verdieping | 2.75 | 2.5 | 0.25 | 0.44075 | 4.4075
2 x Binnenwand | 07 zevende verdieping | 2.75 | 6.675 | 0.6675 | 1.58888 | 15.8887
2 x Binnenwand | 07 zevende verdieping | 2.75 | 3.2 | 0.32 | 0.60575 | 6.0575
Binnenwand | 08 achtste verdieping | 2.75 | 4.45 | 0.445 | 0.977 | 9.77
Binnenwand | 08 achtste verdieping | 2.75 | 3.1 | 0.31 | 0.60575 | 6.0575
2 x Binnenwand | 08 achtste verdieping | 2.75 | 1.25 | 0.125 | 0.097 | 0.97
2 x Binnenwand | 08 achtste verdieping | 2.75 | 1.15 | 0.115 | 0.31625 | 3.1625
5 x Binnenwand | 08 achtste verdieping | 2.75 | 1.25 | 0.125 | 0.34375 | 3.4375
4 x Binnenwand | 08 achtste verdieping | 2.75 | 0.85 | 0.085 | 0.23375 | 2.3375
2 x Binnenwand | 08 achtste verdieping | 2.75 | 2.5 | 0.25 | 0.44075 | 4.4075
2 x Binnenwand | 08 achtste verdieping | 2.75 | 6.675 | 0.6675 | 1.58888 | 15.8887
2 x Binnenwand | 08 achtste verdieping | 2.75 | 3.2 | 0.32 | 0.60575 | 6.0575
3 x Binnenwand | 01 eerste verdieping | 2.75 | 2.125 | 0.2125 | 0.337625 | 3.37625
3 x Binnenwand | 01 eerste verdieping | 2.75 | 3.1 | 0.31 | 0.8525 | 8.525
3 x Binnenwand | 01 eerste verdieping | 2.75 | 4.9 | 0.49 | 1.10075 | 11.0075
3 x Binnenwand | 01 eerste verdieping | 2.75 | 3.15 | 0.315 | 0.86625 | 8.6625
5 x Binnenwand | 01 eerste verdieping | 2.75 | 2.7 | 0.27 | 0.249 | 2.49
3 x Binnenwand | 01 eerste verdieping | 2.75 | 2.95 | 0.295 | 0.81125 | 8.1125
3 x Binnenwand | 01 eerste verdieping | 2.75 | 0.9 | 0.09 | 0.2475 | 2.475
3 x Binnenwand | 01 eerste verdieping | 2.75 | 0.25 | 0.025 | 0.06875 | 0.6875
3 x Binnenwand | 00 begane grond | 3.65 | 1.55 | 0.155 | 0.3425 | 3.425
3 x Binnenwand | 00 begane grond | 3.65 | 6.15 | 0.615 | 1.998 | 19.98
3 x Binnenwand | 00 begane grond | 3.65 | 0.95 | 0.095 | 0.34675 | 3.4675
3 x Binnenwand | 00 begane grond | 3.65 | 1.55 | 0.155 | 0.319 | 3.19
3 x Binnenwand | 00 begane grond | 3.65 | 0.7 | 0.07 | 0.2555 | 2.555
3 x Binnenwand | 00 begane grond | 3.65 | 1.65 | 0.165 | 0.3555 | 3.555
3 x Binnenwand | 00 begane grond | 3.65 | 1.6 | 0.16 | 0.584 | 5.84
Binnenwand | 02 tweede verdieping | 2.75 | 4.3 | 0.43 | 0.93575 | 9.3575
Binnenwand | 02 tweede verdieping | 2.75 | 2.941 | 0.2941 | 0.562025 | 5.62025
Binnenwand | 03 derde verdieping | 2.75 | 4.3 | 0.43 | 0.93575 | 9.3575
Binnenwand | 03 derde verdieping | 2.75 | 2.941 | 0.2941 | 0.562025 | 5.62025
Binnenwand | 04 vierde verdieping | 2.75 | 4.3 | 0.43 | 0.93575 | 9.3575
Binnenwand | 04 vierde verdieping | 2.75 | 2.941 | 0.2941 | 0.562025 | 5.62025
Binnenwand | 05 vijfde verdieping | 2.75 | 4.3 | 0.43 | 0.93575 | 9.3575
Binnenwand | 05 vijfde verdieping | 2.75 | 2.941 | 0.2941 | 0.562025 | 5.62025
Binnenwand | 06 zesde verdieping | 2.75 | 4.3 | 0.43 | 0.93575 | 9.3575
Binnenwand | 06 zesde verdieping | 2.75 | 2.941 | 0.2941 | 0.562025 | 5.62025
Binnenwand | 07 zevende verdieping | 2.75 | 4.3 | 0.43 | 0.93575 | 9.3575
Binnenwand | 07 zevende verdieping | 2.75 | 2.941 | 0.2941 | 0.562025 | 5.62025
Binnenwand | 08 achtste verdieping | 2.75 | 4.3 | 0.43 | 0.93575 | 9.3575
Binnenwand | 08 achtste verdieping | 2.75 | 2.941 | 0.2941 | 0.562025 | 5.62025
2 x Binnenwand | 02 tweede verdieping | 2.75 | 1.35 | 0.135 | 0.37125 | 3.7125
3 x Binnenwand | 02 tweede verdieping | 2.75 | 2.7 | 0.27 | 0.49575 | 4.9575
2 x Binnenwand | 02 tweede verdieping | 2.75 | 7.25 | 0.725 | 1.747 | 17.47
2 x Binnenwand | 03 derde verdieping | 2.75 | 1.35 | 0.135 | 0.37125 | 3.7125
3 x Binnenwand | 03 derde verdieping | 2.75 | 2.7 | 0.27 | 0.49575 | 4.9575
2 x Binnenwand | 03 derde verdieping | 2.75 | 7.25 | 0.725 | 1.747 | 17.47
2 x Binnenwand | 04 vierde verdieping | 2.75 | 1.35 | 0.135 | 0.37125 | 3.7125
3 x Binnenwand | 04 vierde verdieping | 2.75 | 2.7 | 0.27 | 0.49575 | 4.9575
2 x Binnenwand | 04 vierde verdieping | 2.75 | 7.25 | 0.725 | 1.747 | 17.47
2 x Binnenwand | 05 vijfde verdieping | 2.75 | 1.35 | 0.135 | 0.37125 | 3.7125
3 x Binnenwand | 05 vijfde verdieping | 2.75 | 2.7 | 0.27 | 0.49575 | 4.9575
2 x Binnenwand | 05 vijfde verdieping | 2.75 | 7.25 | 0.725 | 1.747 | 17.47
2 x Binnenwand | 06 zesde verdieping | 2.75 | 1.35 | 0.135 | 0.37125 | 3.7125
3 x Binnenwand | 06 zesde verdieping | 2.75 | 2.7 | 0.27 | 0.49575 | 4.9575
2 x Binnenwand | 06 zesde verdieping | 2.75 | 7.25 | 0.725 | 1.747 | 17.47
2 x Binnenwand | 07 zevende verdieping | 2.75 | 1.35 | 0.135 | 0.37125 | 3.7125
3 x Binnenwand | 07 zevende verdieping | 2.75 | 2.7 | 0.27 | 0.49575 | 4.9575
2 x Binnenwand | 07 zevende verdieping | 2.75 | 7.25 | 0.725 | 1.747 | 17.47
2 x Binnenwand | 08 achtste verdieping | 2.75 | 1.35 | 0.135 | 0.37125 | 3.7125
3 x Binnenwand | 08 achtste verdieping | 2.75 | 2.7 | 0.27 | 0.49575 | 4.9575
2 x Binnenwand | 08 achtste verdieping | 2.75 | 7.25 | 0.725 | 1.747 | 17.47
2 x Binnenwand | 02 tweede verdieping | 2.75 | 1.6 | 0.16 | 0.44 | 4.4
2 x Binnenwand | 03 derde verdieping | 2.75 | 1.6 | 0.16 | 0.44 | 4.4
2 x Binnenwand | 04 vierde verdieping | 2.75 | 1.6 | 0.16 | 0.44 | 4.4
2 x Binnenwand | 05 vijfde verdieping | 2.75 | 1.6 | 0.16 | 0.44 | 4.4
2 x Binnenwand | 06 zesde verdieping | 2.75 | 1.6 | 0.16 | 0.44 | 4.4
2 x Binnenwand | 07 zevende verdieping | 2.75 | 1.6 | 0.16 | 0.44 | 4.4
2 x Binnenwand | 08 achtste verdieping | 2.75 | 1.6 | 0.16 | 0.44 | 4.4
Binnenwand | 02 tweede verdieping | 2.75 | 2.55 | 0.255 | 0.4545 | 4.545
Binnenwand | 02 tweede verdieping | 2.75 | 2.9 | 0.29 | 0.304 | 3.04
Binnenwand | 03 derde verdieping | 2.75 | 2.55 | 0.255 | 0.4545 | 4.545
Binnenwand | 03 derde verdieping | 2.75 | 2.9 | 0.29 | 0.304 | 3.04
Binnenwand | 04 vierde verdieping | 2.75 | 2.55 | 0.255 | 0.4545 | 4.545
Binnenwand | 04 vierde verdieping | 2.75 | 2.9 | 0.29 | 0.304 | 3.04
Binnenwand | 05 vijfde verdieping | 2.75 | 2.55 | 0.255 | 0.4545 | 4.545
Binnenwand | 05 vijfde verdieping | 2.75 | 2.9 | 0.29 | 0.304 | 3.04
Binnenwand | 06 zesde verdieping | 2.75 | 2.55 | 0.255 | 0.4545 | 4.545
Binnenwand | 06 zesde verdieping | 2.75 | 2.9 | 0.29 | 0.304 | 3.04
Binnenwand | 07 zevende verdieping | 2.75 | 2.55 | 0.255 | 0.4545 | 4.545
Binnenwand | 07 zevende verdieping | 2.75 | 2.9 | 0.29 | 0.304 | 3.04
Binnenwand | 08 achtste verdieping | 2.75 | 2.55 | 0.255 | 0.4545 | 4.545
Binnenwand | 08 achtste verdieping | 2.75 | 2.9 | 0.29 | 0.304 | 3.04
Binnenwand | 02 tweede verdieping | 2.75 | 7.25216 | 0.725216 | 1.7476 | 17.476
Binnenwand | 02 tweede verdieping | 2.75 | 1.35 | 0.135 | 0.1245 | 1.245
Binnenwand | 02 tweede verdieping | 2.75 | 0.95 | 0.095 | 0.26125 | 2.6125
2 x Binnenwand | 02 tweede verdieping | 2.75 | 1.40216 | 0.140216 | 0.385595 | 3.85595
Binnenwand | 02 tweede verdieping | 2.75 | 2.45 | 0.245 | 0.427 | 4.27
Binnenwand | 02 tweede verdieping | 2.75 | 3 | 0.3 | 0.57825 | 5.7825
Binnenwand | 02 tweede verdieping | 2.75 | 4.65 | 0.465 | 1.27875 | 12.7875
2 x Binnenwand | 02 tweede verdieping | 2.75 | 2.6 | 0.26 | 0.46825 | 4.6825
2 x Binnenwand | 02 tweede verdieping | 2.75 | 3.85 | 0.385 | 0.812 | 8.12
Binnenwand | 03 derde verdieping | 2.75 | 7.25216 | 0.725216 | 1.7476 | 17.476
Binnenwand | 03 derde verdieping | 2.75 | 1.35 | 0.135 | 0.1245 | 1.245
Binnenwand | 03 derde verdieping | 2.75 | 0.95 | 0.095 | 0.26125 | 2.6125
2 x Binnenwand | 03 derde verdieping | 2.75 | 1.40216 | 0.140216 | 0.385595 | 3.85595
Binnenwand | 03 derde verdieping | 2.75 | 2.45 | 0.245 | 0.427 | 4.27
Binnenwand | 03 derde verdieping | 2.75 | 3 | 0.3 | 0.57825 | 5.7825
Binnenwand | 03 derde verdieping | 2.75 | 4.65 | 0.465 | 1.27875 | 12.7875
2 x Binnenwand | 03 derde verdieping | 2.75 | 2.6 | 0.26 | 0.46825 | 4.6825
2 x Binnenwand | 03 derde verdieping | 2.75 | 3.85 | 0.385 | 0.812 | 8.12
Binnenwand | 04 vierde verdieping | 2.75 | 7.25216 | 0.725216 | 1.7476 | 17.476
Binnenwand | 04 vierde verdieping | 2.75 | 1.35 | 0.135 | 0.1245 | 1.245
Binnenwand | 04 vierde verdieping | 2.75 | 0.95 | 0.095 | 0.26125 | 2.6125
2 x Binnenwand | 04 vierde verdieping | 2.75 | 1.40216 | 0.140216 | 0.385595 | 3.85595
Binnenwand | 04 vierde verdieping | 2.75 | 2.45 | 0.245 | 0.427 | 4.27
Binnenwand | 04 vierde verdieping | 2.75 | 3 | 0.3 | 0.57825 | 5.7825
Binnenwand | 04 vierde verdieping | 2.75 | 4.65 | 0.465 | 1.27875 | 12.7875
2 x Binnenwand | 04 vierde verdieping | 2.75 | 2.6 | 0.26 | 0.46825 | 4.6825
2 x Binnenwand | 04 vierde verdieping | 2.75 | 3.85 | 0.385 | 0.812 | 8.12
Binnenwand | 05 vijfde verdieping | 2.75 | 7.25216 | 0.725216 | 1.7476 | 17.476
Binnenwand | 05 vijfde verdieping | 2.75 | 1.35 | 0.135 | 0.1245 | 1.245
Binnenwand | 05 vijfde verdieping | 2.75 | 0.95 | 0.095 | 0.26125 | 2.6125
2 x Binnenwand | 05 vijfde verdieping | 2.75 | 1.40216 | 0.140216 | 0.385595 | 3.85595
Binnenwand | 05 vijfde verdieping | 2.75 | 2.45 | 0.245 | 0.427 | 4.27
Binnenwand | 05 vijfde verdieping | 2.75 | 3 | 0.3 | 0.57825 | 5.7825
Binnenwand | 05 vijfde verdieping | 2.75 | 4.65 | 0.465 | 1.27875 | 12.7875
2 x Binnenwand | 05 vijfde verdieping | 2.75 | 2.6 | 0.26 | 0.46825 | 4.6825
2 x Binnenwand | 05 vijfde verdieping | 2.75 | 3.85 | 0.385 | 0.812 | 8.12
Binnenwand | 06 zesde verdieping | 2.75 | 7.25216 | 0.725216 | 1.7476 | 17.476
Binnenwand | 06 zesde verdieping | 2.75 | 1.35 | 0.135 | 0.1245 | 1.245
Binnenwand | 06 zesde verdieping | 2.75 | 0.95 | 0.095 | 0.26125 | 2.6125
2 x Binnenwand | 06 zesde verdieping | 2.75 | 1.40216 | 0.140216 | 0.385595 | 3.85595
Binnenwand | 06 zesde verdieping | 2.75 | 2.45 | 0.245 | 0.427 | 4.27
Binnenwand | 06 zesde verdieping | 2.75 | 3 | 0.3 | 0.57825 | 5.7825
Binnenwand | 06 zesde verdieping | 2.75 | 4.65 | 0.465 | 1.27875 | 12.7875
2 x Binnenwand | 06 zesde verdieping | 2.75 | 2.6 | 0.26 | 0.46825 | 4.6825
2 x Binnenwand | 06 zesde verdieping | 2.75 | 3.85 | 0.385 | 0.812 | 8.12
Binnenwand | 07 zevende verdieping | 2.75 | 7.25216 | 0.725216 | 1.7476 | 17.476
Binnenwand | 07 zevende verdieping | 2.75 | 1.35 | 0.135 | 0.1245 | 1.245
Binnenwand | 07 zevende verdieping | 2.75 | 0.95 | 0.095 | 0.26125 | 2.6125
2 x Binnenwand | 07 zevende verdieping | 2.75 | 1.40216 | 0.140216 | 0.385595 | 3.85595
Binnenwand | 07 zevende verdieping | 2.75 | 2.45 | 0.245 | 0.427 | 4.27
Binnenwand | 07 zevende verdieping | 2.75 | 3 | 0.3 | 0.57825 | 5.7825
Binnenwand | 07 zevende verdieping | 2.75 | 4.65 | 0.465 | 1.27875 | 12.7875
2 x Binnenwand | 07 zevende verdieping | 2.75 | 2.6 | 0.26 | 0.46825 | 4.6825
2 x Binnenwand | 07 zevende verdieping | 2.75 | 3.85 | 0.385 | 0.812 | 8.12
Binnenwand | 08 achtste verdieping | 2.75 | 7.25216 | 0.725216 | 1.7476 | 17.476
Binnenwand | 08 achtste verdieping | 2.75 | 1.35 | 0.135 | 0.1245 | 1.245
Binnenwand | 08 achtste verdieping | 2.75 | 0.95 | 0.095 | 0.26125 | 2.6125
2 x Binnenwand | 08 achtste verdieping | 2.75 | 1.40216 | 0.140216 | 0.385595 | 3.85595
Binnenwand | 08 achtste verdieping | 2.75 | 2.45 | 0.245 | 0.427 | 4.27
Binnenwand | 08 achtste verdieping | 2.75 | 3 | 0.3 | 0.57825 | 5.7825
Binnenwand | 08 achtste verdieping | 2.75 | 4.65 | 0.465 | 1.27875 | 12.7875
2 x Binnenwand | 08 achtste verdieping | 2.75 | 2.6 | 0.26 | 0.46825 | 4.6825
2 x Binnenwand | 08 achtste verdieping | 2.75 | 3.85 | 0.385 | 0.812 | 8.12
2 x Binnenwand | 02 tweede verdieping | 2.75 | 2.7 | 0.27 | 0.249 | 2.49
Binnenwand | 02 tweede verdieping | 2.75 | 2.9 | 0.29 | 0.55075 | 5.5075
2 x Binnenwand | 03 derde verdieping | 2.75 | 2.7 | 0.27 | 0.249 | 2.49
Binnenwand | 03 derde verdieping | 2.75 | 2.9 | 0.29 | 0.55075 | 5.5075
2 x Binnenwand | 04 vierde verdieping | 2.75 | 2.7 | 0.27 | 0.249 | 2.49
Binnenwand | 04 vierde verdieping | 2.75 | 2.9 | 0.29 | 0.55075 | 5.5075
2 x Binnenwand | 05 vijfde verdieping | 2.75 | 2.7 | 0.27 | 0.249 | 2.49
Binnenwand | 05 vijfde verdieping | 2.75 | 2.9 | 0.29 | 0.55075 | 5.5075
2 x Binnenwand | 06 zesde verdieping | 2.75 | 2.7 | 0.27 | 0.249 | 2.49
Binnenwand | 06 zesde verdieping | 2.75 | 2.9 | 0.29 | 0.55075 | 5.5075
2 x Binnenwand | 07 zevende verdieping | 2.75 | 2.7 | 0.27 | 0.249 | 2.49
Binnenwand | 07 zevende verdieping | 2.75 | 2.9 | 0.29 | 0.55075 | 5.5075
2 x Binnenwand | 08 achtste verdieping | 2.75 | 2.7 | 0.27 | 0.249 | 2.49
Binnenwand | 08 achtste verdieping | 2.75 | 2.9 | 0.29 | 0.55075 | 5.5075
Binnenwand | 02 tweede verdieping | 2.75 | 7.25216 | 0.725216 | 1.50085 | 15.0085
Binnenwand | 02 tweede verdieping | 2.75 | 5.55 | 0.555 | 1.03275 | 10.3275
Binnenwand | 02 tweede verdieping | 2.75 | 4.55 | 0.455 | 1.25125 | 12.5125
Binnenwand | 02 tweede verdieping | 2.75 | 1.325 | 0.1325 | 0.364375 | 3.64375
Binnenwand | 03 derde verdieping | 2.75 | 7.25216 | 0.725216 | 1.50085 | 15.0085
Binnenwand | 03 derde verdieping | 2.75 | 5.55 | 0.555 | 1.03275 | 10.3275
Binnenwand | 03 derde verdieping | 2.75 | 4.55 | 0.455 | 1.25125 | 12.5125
Binnenwand | 03 derde verdieping | 2.75 | 1.325 | 0.1325 | 0.364375 | 3.64375
Binnenwand | 04 vierde verdieping | 2.75 | 7.25216 | 0.725216 | 1.50085 | 15.0085
Binnenwand | 04 vierde verdieping | 2.75 | 5.55 | 0.555 | 1.03275 | 10.3275
Binnenwand | 04 vierde verdieping | 2.75 | 4.55 | 0.455 | 1.25125 | 12.5125
Binnenwand | 04 vierde verdieping | 2.75 | 1.325 | 0.1325 | 0.364375 | 3.64375
Binnenwand | 05 vijfde verdieping | 2.75 | 7.25216 | 0.725216 | 1.50085 | 15.0085
Binnenwand | 05 vijfde verdieping | 2.75 | 5.55 | 0.555 | 1.03275 | 10.3275
Binnenwand | 05 vijfde verdieping | 2.75 | 4.55 | 0.455 | 1.25125 | 12.5125
Binnenwand | 05 vijfde verdieping | 2.75 | 1.325 | 0.1325 | 0.364375 | 3.64375
Binnenwand | 06 zesde verdieping | 2.75 | 7.25216 | 0.725216 | 1.50085 | 15.0085
Binnenwand | 06 zesde verdieping | 2.75 | 5.55 | 0.555 | 1.03275 | 10.3275
Binnenwand | 06 zesde verdieping | 2.75 | 4.55 | 0.455 | 1.25125 | 12.5125
Binnenwand | 06 zesde verdieping | 2.75 | 1.325 | 0.1325 | 0.364375 | 3.64375
Binnenwand | 07 zevende verdieping | 2.75 | 7.25216 | 0.725216 | 1.50085 | 15.0085
Binnenwand | 07 zevende verdieping | 2.75 | 5.55 | 0.555 | 1.03275 | 10.3275
Binnenwand | 07 zevende verdieping | 2.75 | 4.55 | 0.455 | 1.25125 | 12.5125
Binnenwand | 07 zevende verdieping | 2.75 | 1.325 | 0.1325 | 0.364375 | 3.64375
Binnenwand | 08 achtste verdieping | 2.75 | 7.25216 | 0.725216 | 1.50085 | 15.0085
Binnenwand | 08 achtste verdieping | 2.75 | 5.55 | 0.555 | 1.03275 | 10.3275
Binnenwand | 08 achtste verdieping | 2.75 | 4.55 | 0.455 | 1.25125 | 12.5125
Binnenwand | 08 achtste verdieping | 2.75 | 1.325 | 0.1325 | 0.364375 | 3.64375
Binnenwand | 01 eerste verdieping | 2.75 | 0.902164 | 0.0902164 | 0.248095 | 2.48095
Binnenwand | 01 eerste verdieping | 2.75 | 0.4 | 0.04 | 0.11 | 1.1
8 x Binnenwand | 01 eerste verdieping | 2.75 | 2.85 | 0.285 | 0.78375 | 7.8375
4 x Binnenwand | 01 eerste verdieping | 2.75 | 5.75 | 0.575 | 1.08775 | 10.8775
8 x Binnenwand | 01 eerste verdieping | 2.75 | 2.6 | 0.26 | 0.46825 | 4.6825
2 x Binnenwand | 01 eerste verdieping | 2.75 | 1.45 | 0.145 | 0.39875 | 3.9875
2 x Binnenwand | 01 eerste verdieping | 2.75 | 1.25 | 0.125 | 0.34375 | 3.4375
2 x Binnenwand | 01 eerste verdieping | 2.75 | 1.325 | 0.1325 | 0.364375 | 3.64375
4 x Binnenwand | 01 eerste verdieping | 2.75 | 1.50216 | 0.150216 | 0.166345 | 1.66345
4 x Binnenwand | 01 eerste verdieping | 2.75 | 3.5 | 0.35 | 0.71575 | 7.1575
10 x Binnenwand | 01 eerste verdieping | 2.75 | 0.35 | 0.035 | 0.09625 | 0.9625
4 x Binnenwand | 01 eerste verdieping | 2.75 | 0.5 | 0.05 | 0.1375 | 1.375
2 x Binnenwand | 01 eerste verdieping | 2.75 | 1.35 | 0.135 | 0.37125 | 3.7125
2 x Binnenwand | 01 eerste verdieping | 2.75 | 1.4 | 0.14 | 0.385 | 3.85
Binnenwand | 00 begane grond | 3.65 | 3.7 | 0.37 | 1.3505 | 13.505
2 x Binnenwand | 00 begane grond | 3.65 | 2.2 | 0.22 | 0.803 | 8.03
3 x Binnenwand | 00 begane grond | 3.65 | 7.25 | 0.725 | 2.15275 | 21.5275
2 x Binnenwand | 00 begane grond | 3.65 | 0.35 | 0.035 | 0.12775 | 1.2775
Binnenwand | 00 begane grond | 3.65 | 1.1 | 0.11 | 0.15475 | 1.5475
Binnenwand | 00 begane grond | 3.65 | 1.76 | 0.176 | 0.6424 | 6.424
2 x Binnenwand | 00 begane grond | 3.65 | 0.55 | 0.055 | 0.20075 | 2.0075
Binnenwand | 00 begane grond | 3.65 | 1.775 | 0.1775 | 0.401125 | 4.01125
2 x Binnenwand | 00 begane grond | 3.65 | 5.25 | 0.525 | 1.6695 | 16.695
Binnenwand | 00 begane grond | 3.65 | 2.975 | 0.2975 | 0.592375 | 5.92375
Binnenwand | 00 begane grond | 3.65 | 1.2 | 0.12 | 0.438 | 4.38
Binnenwand | 00 begane grond | 3.65 | 1.66 | 0.166 | 0.6059 | 6.059
Binnenwand | 00 begane grond | 3.65 | 1.1 | 0.11 | 0.4015 | 4.015
Binnenwand | 01 eerste verdieping | 2.75 | 3.7 | 0.37 | 1.0175 | 10.175
2 x Binnenwand | 01 eerste verdieping | 2.75 | 2.2 | 0.22 | 0.605 | 6.05
2 x Binnenwand | 01 eerste verdieping | 2.75 | 7.25 | 0.725 | 1.50025 | 15.0025
Binnenwand | 01 eerste verdieping | 2.75 | 1.1 | 0.11 | 0.05575 | 0.5575
Binnenwand | 01 eerste verdieping | 2.75 | 1.76 | 0.176 | 0.484 | 4.84
2 x Binnenwand | 01 eerste verdieping | 2.75 | 0.55 | 0.055 | 0.15125 | 1.5125
2 x Binnenwand | 01 eerste verdieping | 2.75 | 1.775 | 0.1775 | 0.241375 | 2.41375
2 x Binnenwand | 01 eerste verdieping | 2.75 | 5.25 | 0.525 | 1.197 | 11.97
Binnenwand | 01 eerste verdieping | 2.75 | 1.2 | 0.12 | 0.33 | 3.3
Binnenwand | 01 eerste verdieping | 2.75 | 1.66 | 0.166 | 0.4565 | 4.565
Binnenwand | 01 eerste verdieping | 2.75 | 1.1 | 0.11 | 0.3025 | 3.025
Binnenwand | 00 begane grond | 3.65 | 4.5 | 0.45 | 1.39575 | 13.9575
Binnenwand | 00 begane grond | 3.65 | 2.4 | 0.24 | 0.876 | 8.76
Binnenwand | 00 begane grond | 3.65 | 2.4 | 0.24 | 0.62925 | 6.2925

# IfcWall: Basic Wall:22_WA_afbouw_binnenwand 200mm_gen (2)
In: 08 achtste verdieping
Type - PredefinedType: STANDARD
Type - Pset_ReinforcementBarPitchOfWall - Description: Binnenwand
Type - Pset_WallCommon - LoadBearing: no
Classification: 22.10 binnenwanden; niet constructief, algemeen (verzamelniveau) (NL-SfB); Material: ntb_ntb_ntb
Qto_WallBaseQuantities - Height: 2.75 m; Length: 1.2 m; Width: 0.2 m; GrossFootprintArea: 0.24 m2; GrossVolume: 0.66 m3; GrossSideArea: 3.3 m2; NetSideArea: 3.3 m2; NetVolume: 0.66 m3
Pset_EnvironmentalImpactIndicators - Reference: 22_WA_afbouw_binnenwand 200mm_gen; sets with these values: 2
Pset_WallCommon - IsExternal: no; ExtendToStructure: no; Reference: 22_WA_afbouw_binnenwand 200mm_gen

# IfcWall: Basic Wall:22_WA_afbouw_binnenwand 250mm_gen (111)
Type - PredefinedType: STANDARD
Type - Pset_ReinforcementBarPitchOfWall - Description: Binnenwand
Type - Pset_WallCommon - LoadBearing: no
Classification: 22.10 binnenwanden; niet constructief, algemeen (verzamelniveau) (NL-SfB); Material: ntb_ntb_ntb
Qto_WallBaseQuantities - Width: 0.25 m
Pset_EnvironmentalImpactIndicators - Reference: 22_WA_afbouw_binnenwand 250mm_gen; sets with these values: 2
Pset_WallCommon - IsExternal: no; ExtendToStructure: no; Reference: 22_WA_afbouw_binnenwand 250mm_gen
Name | In | Height (m) | Length (m) | GrossFootprintArea (m2) | GrossVolume (m3) | GrossSideArea (m2) = NetSideArea (m2) | NetVolume (m3)
Binnenwand | 02 tweede verdieping | 2.75 | 2.8 | 0.7 | 1.925 | 7.7 | 1.925
2 x Binnenwand | 02 tweede verdieping | 2.75 | 1.815 | 0.45375 | 0.630938 | 2.52375 | 0.630938
2 x Binnenwand | 02 tweede verdieping | 2.75 | 3.075 | 0.76875 | 1.49719 | 5.98875 | 1.49719
4 x Binnenwand | 02 tweede verdieping | 2.75 | 7.25 | 1.8125 | 4.98437 | 19.9375 | 4.98437
2 x Binnenwand | 02 tweede verdieping | 2.75 | 6.675 | 1.66875 | 4.58906 | 18.3562 | 4.58906
Binnenwand | 02 tweede verdieping | 2.75 | 2.7 | 0.675 | 1.85625 | 7.425 | 1.85625
Binnenwand | 03 derde verdieping | 2.75 | 2.8 | 0.7 | 1.925 | 7.7 | 1.925
2 x Binnenwand | 03 derde verdieping | 2.75 | 1.815 | 0.45375 | 0.630938 | 2.52375 | 0.630938
2 x Binnenwand | 03 derde verdieping | 2.75 | 3.075 | 0.76875 | 1.49719 | 5.98875 | 1.49719
4 x Binnenwand | 03 derde verdieping | 2.75 | 7.25 | 1.8125 | 4.98437 | 19.9375 | 4.98437
2 x Binnenwand | 03 derde verdieping | 2.75 | 6.675 | 1.66875 | 4.58906 | 18.3562 | 4.58906
Binnenwand | 03 derde verdieping | 2.75 | 2.7 | 0.675 | 1.85625 | 7.425 | 1.85625
Binnenwand | 04 vierde verdieping | 2.75 | 2.8 | 0.7 | 1.925 | 7.7 | 1.925
2 x Binnenwand | 04 vierde verdieping | 2.75 | 1.815 | 0.45375 | 0.630938 | 2.52375 | 0.630938
2 x Binnenwand | 04 vierde verdieping | 2.75 | 3.075 | 0.76875 | 1.49719 | 5.98875 | 1.49719
4 x Binnenwand | 04 vierde verdieping | 2.75 | 7.25 | 1.8125 | 4.98437 | 19.9375 | 4.98437
2 x Binnenwand | 04 vierde verdieping | 2.75 | 6.675 | 1.66875 | 4.58906 | 18.3562 | 4.58906
Binnenwand | 04 vierde verdieping | 2.75 | 2.7 | 0.675 | 1.85625 | 7.425 | 1.85625
Binnenwand | 05 vijfde verdieping | 2.75 | 2.8 | 0.7 | 1.925 | 7.7 | 1.925
2 x Binnenwand | 05 vijfde verdieping | 2.75 | 1.815 | 0.45375 | 0.630938 | 2.52375 | 0.630938
2 x Binnenwand | 05 vijfde verdieping | 2.75 | 3.075 | 0.76875 | 1.49719 | 5.98875 | 1.49719
4 x Binnenwand | 05 vijfde verdieping | 2.75 | 7.25 | 1.8125 | 4.98437 | 19.9375 | 4.98437
2 x Binnenwand | 05 vijfde verdieping | 2.75 | 6.675 | 1.66875 | 4.58906 | 18.3562 | 4.58906
Binnenwand | 05 vijfde verdieping | 2.75 | 2.7 | 0.675 | 1.85625 | 7.425 | 1.85625
Binnenwand | 06 zesde verdieping | 2.75 | 2.8 | 0.7 | 1.925 | 7.7 | 1.925
2 x Binnenwand | 06 zesde verdieping | 2.75 | 1.815 | 0.45375 | 0.630938 | 2.52375 | 0.630938
2 x Binnenwand | 06 zesde verdieping | 2.75 | 3.075 | 0.76875 | 1.49719 | 5.98875 | 1.49719
4 x Binnenwand | 06 zesde verdieping | 2.75 | 7.25 | 1.8125 | 4.98437 | 19.9375 | 4.98437
2 x Binnenwand | 06 zesde verdieping | 2.75 | 6.675 | 1.66875 | 4.58906 | 18.3562 | 4.58906
Binnenwand | 06 zesde verdieping | 2.75 | 2.7 | 0.675 | 1.85625 | 7.425 | 1.85625
Binnenwand | 07 zevende verdieping | 2.75 | 2.8 | 0.7 | 1.925 | 7.7 | 1.925
2 x Binnenwand | 07 zevende verdieping | 2.75 | 1.815 | 0.45375 | 0.630938 | 2.52375 | 0.630938
2 x Binnenwand | 07 zevende verdieping | 2.75 | 3.075 | 0.76875 | 1.49719 | 5.98875 | 1.49719
4 x Binnenwand | 07 zevende verdieping | 2.75 | 7.25 | 1.8125 | 4.98437 | 19.9375 | 4.98437
2 x Binnenwand | 07 zevende verdieping | 2.75 | 6.675 | 1.66875 | 4.58906 | 18.3562 | 4.58906
Binnenwand | 07 zevende verdieping | 2.75 | 2.7 | 0.675 | 1.85625 | 7.425 | 1.85625
Binnenwand | 01 eerste verdieping | 2.75 | 2.8 | 0.7 | 1.925 | 7.7 | 1.925
Binnenwand | 01 eerste verdieping | 2.75 | 1.815 | 0.45375 | 0.630937 | 2.52375 | 0.630938
2 x Binnenwand | 01 eerste verdieping | 2.75 | 3.075 | 0.76875 | 1.49719 | 5.98875 | 1.49719
8 x Binnenwand | 01 eerste verdieping | 2.75 | 7.25 | 1.8125 | 4.98437 | 19.9375 | 4.98437
2 x Binnenwand | 01 eerste verdieping | 2.75 | 4.5 | 1.125 | 3.09375 | 12.375 | 3.09375
Binnenwand | 01 eerste verdieping | 2.75 | 1.815 | 0.45375 | 0.630938 | 2.52375 | 0.630938
Binnenwand | 01 eerste verdieping | 2.75 | 2.7 | 0.675 | 1.85625 | 7.425 | 1.85625
Binnenwand | 08 achtste verdieping | 2.75 | 2.8 | 0.7 | 1.925 | 7.7 | 1.925
2 x Binnenwand | 08 achtste verdieping | 2.75 | 1.815 | 0.45375 | 0.630938 | 2.52375 | 0.630938
2 x Binnenwand | 08 achtste verdieping | 2.75 | 3.075 | 0.76875 | 1.49719 | 5.98875 | 1.49719
4 x Binnenwand | 08 achtste verdieping | 2.75 | 7.25 | 1.8125 | 4.98437 | 19.9375 | 4.98437
2 x Binnenwand | 08 achtste verdieping | 2.75 | 6.675 | 1.66875 | 4.58906 | 18.3562 | 4.58906
Binnenwand | 08 achtste verdieping | 2.75 | 2.7 | 0.675 | 1.85625 | 7.425 | 1.85625
Binnenwand | 00 begane grond | 3.65 | 7.25 | 1.8125 | 5.99875 | 23.995 | 5.99875
7 x Binnenwand | 00 begane grond | 3.65 | 7.25 | 1.8125 | 6.61562 | 26.4625 | 6.61562
Binnenwand | 00 begane grond | 3.65 | 7.25 | 1.8125 | 5.47 | 21.88 | 5.47
Binnenwand | 00 begane grond | 3.65 | 2.25 | 0.5625 | 2.05312 | 8.2125 | 2.05312
Binnenwand | 00 begane grond | 3.65 | 4.85 | 1.2125 | 4.42562 | 17.7025 | 4.42562

# IfcWall: Basic Wall:28_WA_skelet_wand 200mm_gen (50)
Type - PredefinedType: STANDARD
Type - Pset_ReinforcementBarPitchOfWall - Description: Constructieve wand
Type - Pset_WallCommon - LoadBearing: yes
Classification: 28.20 hoofddraagconstructies; wanden en vloeren, algemeen (verzamelniveau) (NL-SfB); Material: beton_gewapend_prefab-element
Qto_WallBaseQuantities - Width: 0.2 m
Pset_EnvironmentalImpactIndicators - Reference: 28_WA_skelet_wand 200mm_gen; sets with these values: 2
Pset_WallCommon - IsExternal: no; LoadBearing: no; ExtendToStructure: no; Reference: 28_WA_skelet_wand 200mm_gen
Name | In | Height (m) | Length (m) | GrossFootprintArea (m2) | GrossVolume (m3) = NetVolume (m3) | GrossSideArea (m2) = NetSideArea (m2)
Constructieve wand | 02 tweede verdieping | 2.75 | 2.95 | 0.59 | 1.6225 | 8.1125
Constructieve wand | 02 tweede verdieping | 2.75 | 3.7 | 0.74 | 1.075 | 5.375
Constructieve wand | 02 tweede verdieping | 2.75 | 2.75 | 0.55 | 1.5125 | 7.5625
2 x Constructieve wand | 02 tweede verdieping | 2.75 | 3.52 | 0.704 | 1.936 | 9.68
Constructieve wand | 03 derde verdieping | 2.75 | 2.95 | 0.59 | 1.6225 | 8.1125
Constructieve wand | 03 derde verdieping | 2.75 | 3.7 | 0.74 | 1.075 | 5.375
Constructieve wand | 03 derde verdieping | 2.75 | 2.75 | 0.55 | 1.5125 | 7.5625
2 x Constructieve wand | 03 derde verdieping | 2.75 | 3.52 | 0.704 | 1.936 | 9.68
Constructieve wand | 04 vierde verdieping | 2.75 | 2.95 | 0.59 | 1.6225 | 8.1125
Constructieve wand | 04 vierde verdieping | 2.75 | 3.7 | 0.74 | 1.075 | 5.375
Constructieve wand | 04 vierde verdieping | 2.75 | 2.75 | 0.55 | 1.5125 | 7.5625
2 x Constructieve wand | 04 vierde verdieping | 2.75 | 3.52 | 0.704 | 1.936 | 9.68
Constructieve wand | 05 vijfde verdieping | 2.75 | 2.95 | 0.59 | 1.6225 | 8.1125
Constructieve wand | 05 vijfde verdieping | 2.75 | 3.7 | 0.74 | 1.075 | 5.375
Constructieve wand | 05 vijfde verdieping | 2.75 | 2.75 | 0.55 | 1.5125 | 7.5625
2 x Constructieve wand | 05 vijfde verdieping | 2.75 | 3.52 | 0.704 | 1.936 | 9.68
Constructieve wand | 06 zesde verdieping | 2.75 | 2.95 | 0.59 | 1.6225 | 8.1125
Constructieve wand | 06 zesde verdieping | 2.75 | 3.7 | 0.74 | 1.075 | 5.375
Constructieve wand | 06 zesde verdieping | 2.75 | 2.75 | 0.55 | 1.5125 | 7.5625
2 x Constructieve wand | 06 zesde verdieping | 2.75 | 3.52 | 0.704 | 1.936 | 9.68
Constructieve wand | 07 zevende verdieping | 2.75 | 2.95 | 0.59 | 1.6225 | 8.1125
Constructieve wand | 07 zevende verdieping | 2.75 | 3.7 | 0.74 | 1.075 | 5.375
Constructieve wand | 07 zevende verdieping | 2.75 | 2.75 | 0.55 | 1.5125 | 7.5625
2 x Constructieve wand | 07 zevende verdieping | 2.75 | 3.52 | 0.704 | 1.936 | 9.68
Constructieve wand | 01 eerste verdieping | 2.75 | 2.95 | 0.59 | 1.6225 | 8.1125
Constructieve wand | 01 eerste verdieping | 2.75 | 3.7 | 0.74 | 1.075 | 5.375
Constructieve wand | 01 eerste verdieping | 2.75 | 2.75 | 0.55 | 1.5125 | 7.5625
2 x Constructieve wand | 01 eerste verdieping | 2.75 | 3.52 | 0.704 | 1.936 | 9.68
Constructieve wand | 08 achtste verdieping | 2.75 | 2.95 | 0.59 | 1.6225 | 8.1125
Constructieve wand | 08 achtste verdieping | 2.75 | 3.7 | 0.74 | 1.075 | 5.375
Constructieve wand | 08 achtste verdieping | 2.75 | 2.75 | 0.55 | 1.5125 | 7.5625
2 x Constructieve wand | 08 achtste verdieping | 2.75 | 3.52 | 0.704 | 1.936 | 9.68
2 x Constructieve wand | -1 kelder | 2.95 | 2.75 | 0.55 | 1.6225 | 8.1125
Constructieve wand | -1 kelder | 2.95 | 10.05 | 2.01 | 3.9825 | 19.9125
2 x Constructieve wand | -1 kelder | 2.95 | 3.52 | 0.704 | 2.0768 | 10.384
Constructieve wand | 00 begane grond | 3.65 | 2.95 | 0.59 | 2.1535 | 10.7675
Constructieve wand | 00 begane grond | 3.65 | 3.7 | 0.74 | 2.701 | 13.505
Constructieve wand | 00 begane grond | 3.65 | 2.75 | 0.55 | 2.0075 | 10.0375
2 x Constructieve wand | 00 begane grond | 3.65 | 6.12 | 1.224 | 4.4676 | 22.338

# IfcWall: Basic Wall:28_WA_skelet_wand 250mm_gen (62)
Type - PredefinedType: STANDARD
Type - Pset_ReinforcementBarPitchOfWall - Description: Constructieve wand
Type - Pset_WallCommon - LoadBearing: yes
Classification: 28.20 hoofddraagconstructies; wanden en vloeren, algemeen (verzamelniveau) (NL-SfB); Material: beton_gewapend_ihw
Qto_WallBaseQuantities - Width: 0.25 m
Pset_EnvironmentalImpactIndicators - Reference: 28_WA_skelet_wand 250mm_gen; sets with these values: 2
Pset_WallCommon - IsExternal: no; Reference: 28_WA_skelet_wand 250mm_gen; LoadBearing: no; ExtendToStructure: no
Name | In | Height (m) | Length (m) | GrossFootprintArea (m2) | GrossVolume (m3) | GrossSideArea (m2) = NetSideArea (m2) | NetVolume (m3)
Constructieve wand | 02 tweede verdieping | 2.75 | 24.1 | 6.025 | 16.5688 | 66.275 | 16.5688
2 x Constructieve wand | 02 tweede verdieping | 2.75 | 24.1 | 6.025 | 14.5719 | 58.2875 | 14.5719
Constructieve wand | 02 tweede verdieping | 2.75 | 24.1 | 6.025 | 16.5688 | 66.275 | 16.5687
Constructieve wand | 02 tweede verdieping | 2.75 | 7.25 | 1.8125 | 3.6475 | 14.59 | 3.6475
Constructieve wand | 02 tweede verdieping | 2.75 | 7.25 | 1.8125 | 3.7075 | 14.83 | 3.7075
Constructieve wand | 03 derde verdieping | 2.75 | 24.1 | 6.025 | 16.5688 | 66.275 | 16.5688
2 x Constructieve wand | 03 derde verdieping | 2.75 | 24.1 | 6.025 | 14.5719 | 58.2875 | 14.5719
Constructieve wand | 03 derde verdieping | 2.75 | 24.1 | 6.025 | 16.5688 | 66.275 | 16.5687
Constructieve wand | 03 derde verdieping | 2.75 | 7.25 | 1.8125 | 3.6475 | 14.59 | 3.6475
Constructieve wand | 03 derde verdieping | 2.75 | 7.25 | 1.8125 | 3.7075 | 14.83 | 3.7075
Constructieve wand | 04 vierde verdieping | 2.75 | 24.1 | 6.025 | 16.5688 | 66.275 | 16.5688
2 x Constructieve wand | 04 vierde verdieping | 2.75 | 24.1 | 6.025 | 14.5719 | 58.2875 | 14.5719
Constructieve wand | 04 vierde verdieping | 2.75 | 24.1 | 6.025 | 16.5688 | 66.275 | 16.5687
Constructieve wand | 04 vierde verdieping | 2.75 | 7.25 | 1.8125 | 3.6475 | 14.59 | 3.6475
Constructieve wand | 04 vierde verdieping | 2.75 | 7.25 | 1.8125 | 3.7075 | 14.83 | 3.7075
Constructieve wand | 05 vijfde verdieping | 2.75 | 24.1 | 6.025 | 16.5688 | 66.275 | 16.5688
2 x Constructieve wand | 05 vijfde verdieping | 2.75 | 24.1 | 6.025 | 14.5719 | 58.2875 | 14.5719
Constructieve wand | 05 vijfde verdieping | 2.75 | 24.1 | 6.025 | 16.5688 | 66.275 | 16.5687
Constructieve wand | 05 vijfde verdieping | 2.75 | 7.25 | 1.8125 | 3.6475 | 14.59 | 3.6475
Constructieve wand | 05 vijfde verdieping | 2.75 | 7.25 | 1.8125 | 3.7075 | 14.83 | 3.7075
Constructieve wand | 06 zesde verdieping | 2.75 | 24.1 | 6.025 | 16.5688 | 66.275 | 16.5688
2 x Constructieve wand | 06 zesde verdieping | 2.75 | 24.1 | 6.025 | 14.5719 | 58.2875 | 14.5719
Constructieve wand | 06 zesde verdieping | 2.75 | 24.1 | 6.025 | 16.5688 | 66.275 | 16.5687
Constructieve wand | 06 zesde verdieping | 2.75 | 7.25 | 1.8125 | 3.6475 | 14.59 | 3.6475
Constructieve wand | 06 zesde verdieping | 2.75 | 7.25 | 1.8125 | 3.7075 | 14.83 | 3.7075
Constructieve wand | 07 zevende verdieping | 2.75 | 24.1 | 6.025 | 16.5688 | 66.275 | 16.5688
2 x Constructieve wand | 07 zevende verdieping | 2.75 | 24.1 | 6.025 | 14.5719 | 58.2875 | 14.5719
Constructieve wand | 07 zevende verdieping | 2.75 | 24.1 | 6.025 | 16.5688 | 66.275 | 16.5687
Constructieve wand | 07 zevende verdieping | 2.75 | 7.25 | 1.8125 | 3.6475 | 14.59 | 3.6475
Constructieve wand | 07 zevende verdieping | 2.75 | 7.25 | 1.8125 | 3.7075 | 14.83 | 3.7075
2 x Constructieve wand | 01 eerste verdieping | 2.75 | 33.35 | 8.3375 | 17.6481 | 70.5925 | 17.6481
4 x Constructieve wand | 01 eerste verdieping | 2.75 | 10.8 | 2.7 | 7.425 | 29.7 | 7.425
Constructieve wand | 01 eerste verdieping | 2.75 | 7.25 | 1.8125 | 4.98438 | 19.9375 | 4.98438
Constructieve wand | 01 eerste verdieping | 2.75 | 7.25 | 1.8125 | 4.98437 | 19.9375 | 4.98437
Constructieve wand | 08 achtste verdieping | 2.75 | 24.1 | 6.025 | 16.5688 | 66.275 | 16.5688
2 x Constructieve wand | 08 achtste verdieping | 2.75 | 24.1 | 6.025 | 14.5719 | 58.2875 | 14.5719
Constructieve wand | 08 achtste verdieping | 2.75 | 24.1 | 6.025 | 16.5688 | 66.275 | 16.5687
Constructieve wand | 08 achtste verdieping | 2.75 | 7.25 | 1.8125 | 3.6475 | 14.59 | 3.6475
Constructieve wand | 08 achtste verdieping | 2.75 | 7.25 | 1.8125 | 3.7075 | 14.83 | 3.7075
Constructieve wand | -1 kelder | 2.95 | 10.05 | 2.5125 | 7.41187 | 29.6475 | 7.41188
Constructieve wand | -1 kelder | 2.95 | 10.3 | 2.575 | 7.59625 | 30.385 | 7.59625
Constructieve wand | -1 kelder | 2.95 | 7.5 | 1.875 | 4.91437 | 19.6575 | 4.91437
Constructieve wand | -1 kelder | 2.95 | 7.75 | 1.9375 | 5.09875 | 20.395 | 5.09875
Constructieve wand | 01 eerste verdieping | 2.75 | 6.35 | 1.5875 | 4.36562 | 17.4625 | 4.36562
Constructieve wand | 01 eerste verdieping | 2.75 | 6.35 | 1.5875 | 4.36562 | 17.4625 | 4.36563
Constructieve wand | 00 begane grond | 3.65 | 33.35 | 8.3375 | 26.3517 | 105.407 | 26.3517
Constructieve wand | 00 begane grond | 3.65 | 33.35 | 8.3375 | 28.6606 | 114.642 | 28.6606
Constructieve wand | 00 begane grond | 3.65 | 7.25 | 1.8125 | 6.61563 | 26.4625 | 6.61562
Constructieve wand | 00 begane grond | 3.65 | 33.35 | 8.3375 | 24.7806 | 99.1225 | 24.7806
Constructieve wand | 00 begane grond | 3.65 | 7.25 | 1.8125 | 6.61562 | 26.4625 | 6.61562
Constructieve wand | 00 begane grond | 3.65 | 33.35 | 8.3375 | 23.5806 | 94.3225 | 23.5806
